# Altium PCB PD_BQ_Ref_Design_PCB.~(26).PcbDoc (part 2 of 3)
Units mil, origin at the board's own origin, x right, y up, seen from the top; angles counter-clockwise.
Board outline 2000 x 3000 mil, 4 copper layers (Top Layer, Signal Layer 1, Signal Layer 2, Bottom Layer), stack 61.2 mil thick; 124 components, 53 nets, 359 pads, 494 vias.
Unrouted connection lines stored in the file: 227.

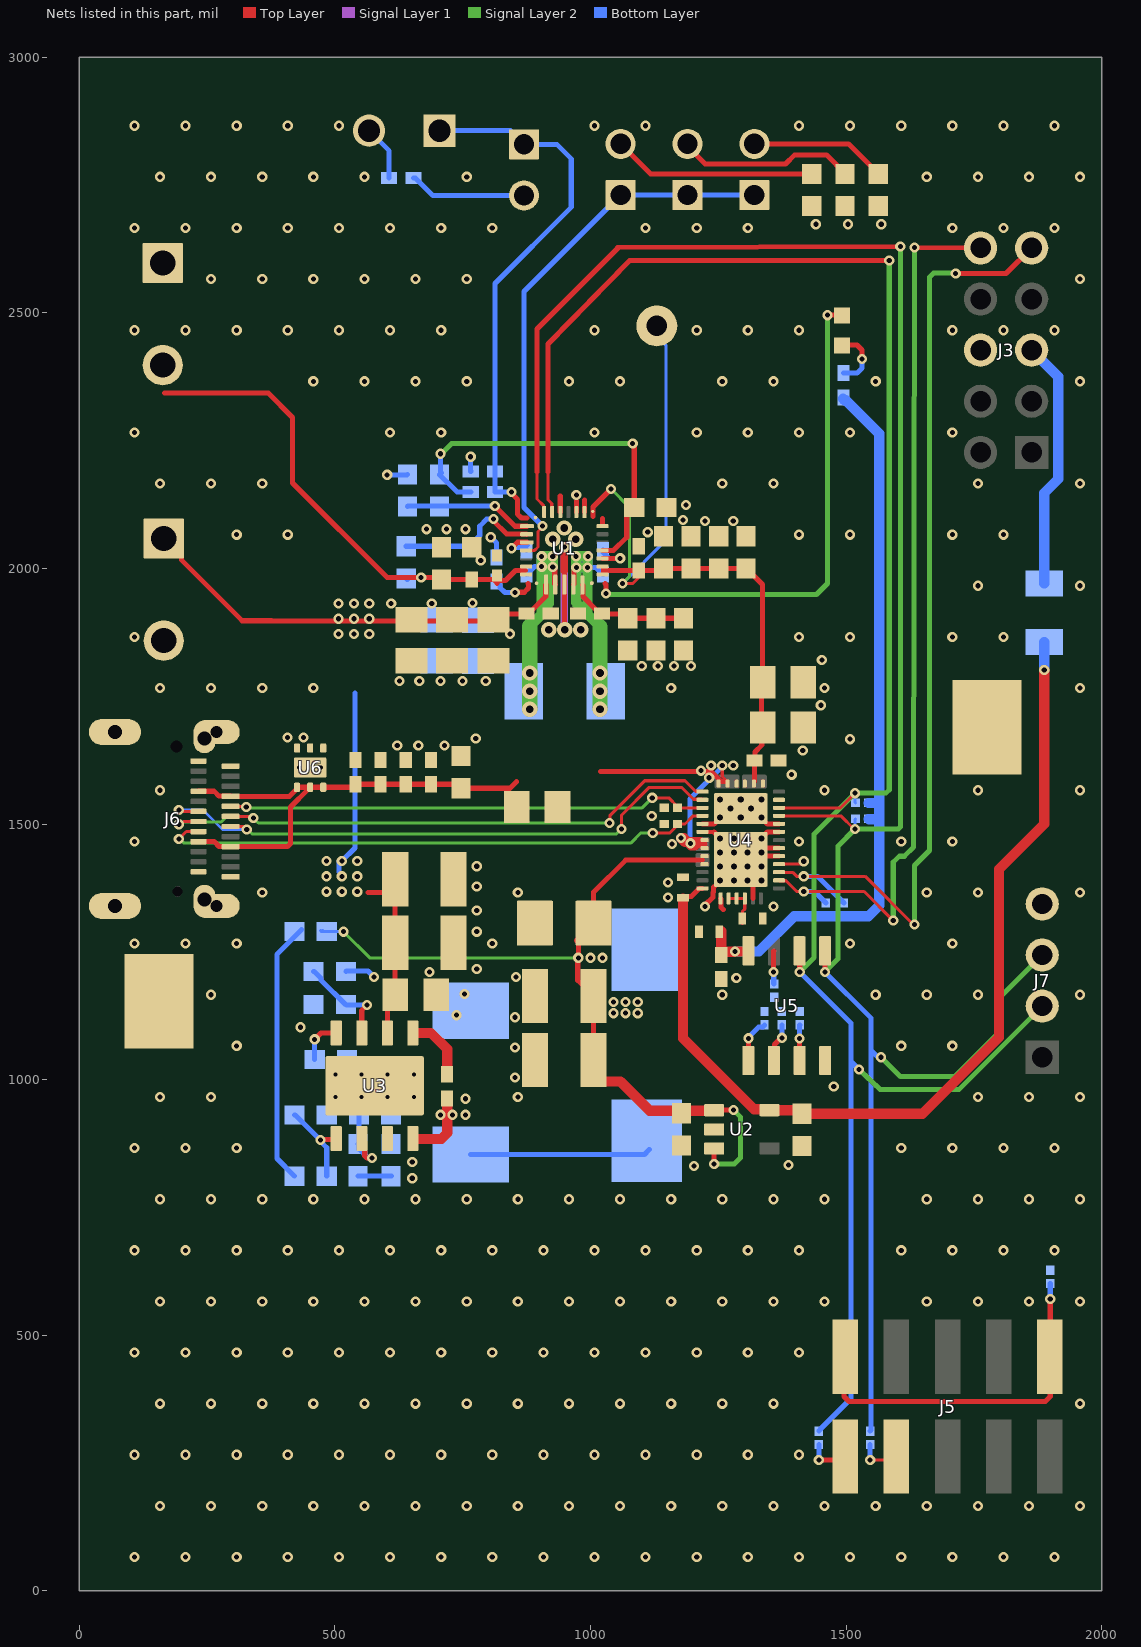
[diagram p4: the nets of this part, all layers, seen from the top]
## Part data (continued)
Logo4: library part CMP-0074769-1
LOGO5: library part CMP-0074837-1, "IEC 61010-1 Hot Surface Warning"
NT1: library part CMP-0078142-3, "Single point connection between nets.", Manufacturer=N/A
R1: library part CMP-0022736-4, "RES, 100, 1%, 0.1 W, 0603", Manufacturer=Yageo, Power_W=100mW, Supplier Part Number 1=311-100HRCT-ND, TempCo="100 ppm/C", Tolerance_%=1%, Value2=0.1W, Value_Code=100R, ValueDisplayed=100
R2: library part CMP-0026232-2, "RES, 2.21 k, 1%, 0.063 W, AEC-Q200 Grade 0, 0402", Manufacturer=Vishay-Dale, Power_W=63mW, Supplier Part Number 1=541-2.21KLCT-ND, TempCo="100 ppm/C", Tolerance_%=1%, Value2=0.063W, Value_Code=2k21, ValueDisplayed=2.21k
R3: library part CMP-0026464-2, "RES, 5.23 k, 1%, 0.063 W, AEC-Q200 Grade 0, 0402", Manufacturer=Vishay-Dale, PartNumber=CRCW04025K23FKED, Power_W=63mW, Supplier Part Number 1=541-5.23KLCT-ND, TempCo="100 ppm/C", Tolerance_%=1%, Value2=0.063W, Value_Code=5k23, ValueDisplayed=5.23k
R4: library part CMP-0022788-4, "RES, 137 k, 1%, 0.1 W, 0603", Manufacturer=Yageo, Power_W=100mW, Supplier Part Number 1=311-137KHRCT-ND, TempCo="100 ppm/C", Tolerance_%=1%, Value2=0.1W, Value_Code=137k
R5: library part CMP-0026284-2, "RES, 30.1 k, 1%, 0.063 W, AEC-Q200 Grade 0, 0402", Manufacturer=Vishay-Dale, PartNumber=CRCW040230K1FKED, Power_W=63mW, Supplier Part Number 1=541-30.1KLCT-ND, TempCo="100 ppm/C", Tolerance_%=1%, Value2=0.063W, Value_Code=30k1, ValueDisplayed=30.1k
R6: library part CMP-0022735-5, "RES, 100 k, 1%, 0.1 W, 0603", Manufacturer=Yageo, Power_W=100mW, Supplier Part Number 1=311-100KHRCT-ND, TempCo="100 ppm/C", Tolerance_%=1%, Value2=0.1W, Value_Code=100k
R7: library part CMP-0025958-3, "RES, 10.0 k, 1%, 0.063 W, AEC-Q200 Grade 0, 0402", Manufacturer=Vishay-Dale, PartNumber=CRCW040210K0FKED, Power_W=63mW, Supplier Part Number 1=541-10.0KLCT-ND, TempCo="100 ppm/C", Tolerance_%=1%, Value2=0.063W, Value_Code=10k0, ValueDisplayed=10.0k
R8: library part CMP-0023246-5, "RES, 6.04 k, 1%, 0.1 W, 0603", Manufacturer=Yageo, Power_W=100mW, Supplier Part Number 1=311-6.04KHRCT-ND, TempCo="100 ppm/C", Tolerance_%=1%, Value2=0.1W, Value_Code=6k04, ValueDisplayed=6.04k
R9: library part CMP-0022000-4, "RES, 10.5 k, 1%, 0.1 W, AEC-Q200 Grade 0, 0603", Manufacturer=Vishay-Dale, Power_W=100mW, Supplier Part Number 1=541-10.5KHCT-ND, TempCo="100 ppm/C", Tolerance_%=1%, Value2=0.1W, Value_Code=10k5, ValueDisplayed=10.5k
R10: library part CMP-0022089-4, "RES, 17.4 k, 1%, 0.1 W, AEC-Q200 Grade 0, 0603", Manufacturer=Vishay-Dale, Power_W=100mW, Supplier Part Number 1=541-17.4KHCT-ND, TempCo="100 ppm/C", Tolerance_%=1%, Value2=0.1W, Value_Code=17k4, ValueDisplayed=17.4k
R11: library part CMP-0017299-3, "RES, 10.0, 1%, 0.25 W, AEC-Q200 Grade 0, 1206", Manufacturer=Panasonic, Power_W=250mW, Supplier Part Number 1=P10.0FCT-ND, TempCo="100 ppm/C", Tolerance_%=1%, Value2=0.25W, Value_Code=10R0, ValueDisplayed=10.0
R12: library part CMP-0022483-4, "RES, 51.1, 1%, 0.1 W, AEC-Q200 Grade 0, 0603", Manufacturer=Vishay-Dale, Power_W=100mW, Supplier Part Number 1=541-51.1HCT-ND, TempCo="100 ppm/C", Tolerance_%=1%, Value2=0.1W, Value_Code=51R1, ValueDisplayed=51.1
R13: library part CMP-0022546-4, "RES, 665 k, 1%, 0.1 W, AEC-Q200 Grade 0, 0603", Manufacturer=Vishay-Dale, Power_W=100mW, Supplier Part Number 1=541-665KHCT-ND, TempCo="100 ppm/C", Tolerance_%=1%, Value2=0.1W, Value_Code=665k
R14: library part CMP-0021999-4, "RES, 10.2 k, 1%, 0.1 W, AEC-Q200 Grade 0, 0603", Manufacturer=Vishay-Dale, Power_W=100mW, Supplier Part Number 1=541-10.2KHCT-ND, TempCo="100 ppm/C", Tolerance_%=1%, Value2=0.1W, Value_Code=10k2, ValueDisplayed=10.2k
R15: library part CMP-0022036-4, "RES, 130 k, 1%, 0.1 W, AEC-Q200 Grade 0, 0603", Manufacturer=Vishay-Dale, Power_W=100mW, Supplier Part Number 1=541-130KHCT-ND, TempCo="100 ppm/C", Tolerance_%=1%, Value2=0.1W, Value_Code=130k
R16: library part CMP-0022137-4, "RES, 1.96 k, 1%, 0.1 W, AEC-Q200 Grade 0, 0603", Manufacturer=Vishay-Dale, Power_W=100mW, Supplier Part Number 1=541-1.96KHCT-ND, TempCo="100 ppm/C", Tolerance_%=1%, Value2=0.1W, Value_Code=1k96, ValueDisplayed=1.96k
R17: library part CMP-0022360-4, "RES, 37.4 k, 1%, 0.1 W, AEC-Q200 Grade 0, 0603", Manufacturer=Vishay-Dale, Power_W=100mW, Supplier Part Number 1=541-37.4KHCT-ND, TempCo="100 ppm/C", Tolerance_%=1%, Value2=0.1W, Value_Code=37k4, ValueDisplayed=37.4k
R21 R22 R24 R25: library part CMP-0027272-3, "RES, 2.20 k, 1%, 0.05 W, 0201", Manufacturer=Vishay-Dale, Power_W=50mW, Supplier Part Number 1=541-2.20KAABCT-ND, TempCo="100 ppm/C", Tolerance_%=1%, Value2=0.05W, Value_Code=2k20, ValueDisplayed=2.20k
R26 R27 R29: library part CMP-0027008-4, "RES, 0, 5%, 0.05 W, 0201", Manufacturer=Vishay-Dale, Power_W=50mW, Supplier Part Number 1=72M6743, TempCo=ppm/C, Tolerance_%=5%, Value2=0.05W, Value_Code=0000, ValueDisplayed=0
R28 R30 R31 R32: library part CMP-0027262-3, "RES, 10.0 k, 1%, 0.05 W, 0201", Manufacturer=Vishay-Dale, Power_W=50mW, Supplier Part Number 1=541-10.0KAABCT-ND, TempCo="100 ppm/C", Tolerance_%=1%, Value2=0.05W, Value_Code=10k0, ValueDisplayed=10.0k
SH-J1 SH-J2: library part CMP-0003623-1, "Shunt, 100mil, Gold plated, Black", Alternate Manufacturer=3M, Alternate PartNumber=969102-0000-DA, Manufacturer=Samtec, Supplier Part Number 1=SNT-100-BK-G-ND
TP1: library part CMP-0055137-1, "Test Point, Miniature, Red, TH", Color=Red, Manufacturer=Keystone, Supplier Part Number 1=36-5000-ND
TP2 TP3: library part CMP-0055153-1, "Test Point, Compact, SMT", Manufacturer=Keystone, Supplier Part Number 1=36-5016TR-ND
U1: library part CMP-0088656-1, "BQ2579x HotRod", Manufacturer="Texas Instruments", Operating Temperature Range=to
U2: library part CMP-0074640-3, "500-mA, Low IQ, Small Size, Low Dropout Regulator, DBV0005A (SOT-23-5)", Alternate Manufacturer="Texas Instruments"
U3: library part CMP-0067056-2, "3.5V to 28V Input, 5A, 570kHz Step-Down Converter with Eco-mode, DDA0008E (SOIC-8)", Alternate Manufacturer="Texas Instruments", Alternate PartNumber=TPS54531DDA
U4: library part CMP-0090338-5, "USB Type-C and USB PD Controller with Integrated Power Switches Optimized for Power Applications", Manufacturer="Texas Instruments", Max Supply Voltage=22V, Min Supply Voltage=3V, Operating Temperature Range="-40°C to +125°C"
U5: library part CMP-0005314-2, "256 kb I2C CMOS Serial EEPROM, SOIC-8", Manufacturer="ON Semiconductor", Supplier Part Number 1=CAT24C256WI-G-ND
U6: library part CMP-0077834-1, "22-V Precision Surge Protection Clamp, DRV0006A (WSON-6)", Alternate Manufacturer="Texas Instruments"
ZZ1: library part CMP-0003616-3

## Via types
v1: diameter 20, hole 10, Top Layer to Bottom Layer, tented both sides, 445 vias
v2: diameter 23.62, hole 11.81, Top Layer to Bottom Layer, 24 vias
v3: diameter 30, hole 15, Top Layer to Bottom Layer, tented both sides, 12 vias
v4: diameter 19.68, hole 7.87, Top Layer to Bottom Layer, tented both sides, 10 vias
v5: diameter 20, hole 10, Top Layer to Bottom Layer, 3 vias

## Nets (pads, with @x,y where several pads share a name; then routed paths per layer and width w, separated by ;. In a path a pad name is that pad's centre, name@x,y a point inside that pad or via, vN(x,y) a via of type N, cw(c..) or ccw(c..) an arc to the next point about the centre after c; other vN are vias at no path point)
AGND: C22.2 J3.6 J4.2 NT1.2 R5.1 R6.1 R7.1 R8.1 R9.1 R10.1 U1.10 U1.11 U1.13 | length 298.5
  Top Layer w10: 940.94,2141.73 941.06,2141.61 U1.13@941.06,2110.14 ; 972.44,2131.89 972.44,2110.25 U1.11@972.56,2110.14 ; 988.19,2133.86 988.31,2133.74 U1.10@988.31,2110.14
  Bottom Layer w10: J4.2@566.93,2856.3 606.3,2816.93 R7.1@606.3,2763.78 ; v1(602.36,2183.07) 640.93,2183.07 R6.1@641.92,2184.06 ; v1(765.75,2218.5) 765.75,2190.08 R5.1@765.87,2189.96 ; v1(805.12,2061.02) 816.06,2050.08 C22.2@816.06,2021.65
  other v1: 972.44,2143.7 1440.94,2673.23 1503.94,2673.23 1568.9,2673.23
BAT: C19.1 C20.1 C21.1 J2.2 R1.1 U1.22 U1.23 | length 977.6
  Top Layer w10: 167.32,2342.91 369.68,2342.91 417.32,2295.28 417.32,2167.32 602.36,1982.28 v1(668.92,1982.28) 704.84,1982.28 C21.1@708.78,1978.35 C20.1@767.83,1978.35 811.14,1978.35 817.05,1972.44 ; 817.05,1970.47 817.05,1972.44 ; 873.15,1996.06 853.46,1996.06 833.89,1976.49 821.1,1976.49 817.05,1972.44
  Bottom Layer w10: R1.1@639.76,1980.31 641.73,1978.35 645.67,1982.28 v1(668.92,1982.28)
C_CC1: C42.1 J6.A5 U4.28 | length 942.2
  Top Layer w6: J6.A5@296.26,1534.45 296.75,1533.96 326.28,1533.96 v1(326.77,1533.46) ; v1(1120.87,1551.18) 1153.44,1551.18 1170.47,1534.15 C42.1@1170.47,1531.5 1219.12,1531.5 U4.28@1219.3,1531.68
  Signal Layer 2 w6: v1(326.77,1533.46) 328.74,1531.5 1101.18,1531.5 v1(1120.87,1551.18)
C_CC2: C41.1 J6.B5 U4.29 | length 1095.8
  Top Layer w6: v1(194.88,1470.47) 209.65,1485.24 J6.B5@233.27,1485.24 ; v1(1122.05,1482.28) 1155.41,1482.28 1170.47,1497.35 C41.1@1170.47,1500 1185.04,1500 1200.97,1515.93 U4.29@1219.3,1515.93
  Signal Layer 2 w6: v1(194.88,1470.47) 197.52,1470.47 205.4,1462.6 1078.74,1462.6 1098.43,1482.28 v1(1122.05,1482.28)
C_USB_N: J6.A7 J6.B7 U4.27 | length 1182
  Top Layer w6: v1(194.88,1527.56) 197.83,1524.61 J6.B7@233.27,1524.61 ; J6.A7@296.26,1495.08 321.85,1495.08 v1(327.7,1489.23) ; v1(1061.02,1490.16) 1061.02,1517.72 1114.98,1571.68 1178.32,1571.68 1201.64,1548.36 1218.36,1548.36 U4.27@1219.3,1547.43
  Signal Layer 2 w6: v1(327.7,1489.23) 329.3,1489.23 338.21,1480.32 1050.51,1480.32 v1@1060.69,1490.49
  Bottom Layer w6: v1(194.88,1527.56) 242.13,1527.56 280.45,1489.23 v1(327.7,1489.23) ; v1@1060.35,1490.16 v1(1061.02,1490.16)
C_USB_P: J6.A6 J6.B6 U4.26 | length 1175.4
  Top Layer w6: v1(194.88,1499.56) 198.67,1499.56 204.03,1504.92 J6.B6@233.27,1504.92 ; J6.A6@296.26,1514.76 333.81,1514.76 336.76,1511.81 v1(340.55,1511.81) ; v1(1037.4,1501.97) 1037.95,1502.51 1037.95,1516.29 1106.3,1584.65 1185.04,1584.65 1205.58,1564.11 1218.36,1564.11 U4.26@1219.3,1563.17
  Signal Layer 2 w6: v1(194.88,1499.56) 198.67,1499.56 203.05,1503.94 277.56,1503.94 288.39,1514.76 330.04,1514.76 330.31,1514.49 337.87,1514.49 v1(340.55,1511.81) ; v1@339.07,1513.29 350.39,1501.97 v1(1037.4,1501.97)
GND: C2.1 C3.1 C4.1 C5.1 C6.2 C8.1 C9.1 C10.1 C11.2 C12.2 C13.2 C14.2 C15.2 C16.2 C17.2 C18.2 C19.2 C20.2 C21.2 C23.1 C24.1 C26.2 C27.2 C28.2 C29.2 C30.2 C31.2 C33.2 C34.2 C35.2 C36.2 C37.2 C38.2 C39.2 C40.2 C41.2 C42.2 C43.2 C44.2 C45.1 C46.1 C47.1 C48.1 D2.2 J1.2 J2.1 J6.A1 J6.A12 J6.B1 J6.B12 J6.S1 J6.S2 J6.S3 J6.S4 J7.4 NT1.1 R15.1 R16.1 R17.1 R28.1 R29.1 R30.1 R31.1 R32.1 TP2.1 TP3.1 U1.27 U2.2 U3.7 U3.9@577.76,987.91 U4.10 U4.11 U4.12 U4.14 U4.18 U4.31 U4.39 U5.4 U6.1 U6.2 U6.3 U6.7@451.77,1610.24 | length 871.8
  Top Layer w6: U4.10@1368.91,1421.44 1411.6,1421.44 v1(1417.32,1427.17)
  Top Layer w8: U4.31@1219.3,1484.43 1241.74,1484.43
  Top Layer w10: 948.94,1996.06 U1.27@948.94,1968.4 948.94,1879.92 v3(949.92,1879.92) ; v1(1224.41,1338.58) 1224.41,1341.29 1239.73,1356.61 1239.73,1365.89 1241.11,1367.27 1241.11,1376.32 1281.21,1416.42 1294.1,1429.31 U4.39@1294.1,1430.69 ; 1241.74,1484.43 1281.21,1444.96 U4.39@1294.1,1432.07 ; U4.39@1307.69,1417.11 U4.39@1294.1,1430.69 ; U4.39@1307.69,1444.28 U4.39@1294.1,1430.69 ; U4.39@1315.66,1453.63 1346.46,1484.43 U4.14@1368.91,1484.43 ; U4.39@1316.35,1452.94 U4.12@1368.91,1452.94 U4.39@1334.26,1452.94 ; 1317.72,1354.51 U4.39@1317.72,1407.07 ; U4.39@1334.26,1437.19 U4.11@1368.91,1437.19
  Top Layer w15: 948.94,1996.06 v1@948.94,2041.53
  Signal Layer 1 w15: v1(948.94,2041.55) 949.06,2041.43 949.06,1880.79 v3(949.92,1879.92)
  other v1: 108,66 208,66 308,66 408,66 508,66 608,66 708,66 808,66 908,66 1008,66 1108,66 1208,66 1308,66 1408,66 1508,66 1608,66 1708,66 1808,66 1908,66 158,166 258,166 358,166 458,166 558,166 658,166 758,166 858,166 958,166 1058,166 1158,166 1258,166 1358,166 1458,166 1558,166 1658,166 1758,166 1858,166 1958,166 108,266 208,266 308,266 408,266 508,266 608,266 708,266 808,266 908,266 1008,266 1108,266 1208,266 1308,266 1408,266 158,366 258,366 358,366 458,366 558,366 658,366 758,366 858,366 958,366 1058,366 1158,366 1258,366 1358,366 1958,366 108,466 208,466 308,466 408,466 508,466 608,466 708,466 808,466 908,466 1008,466 1108,466 1208,466 1308,466 1408,466 158,566 258,566 358,566 458,566 558,566 658,566 758,566 858,566 958,566 1058,566 1158,566 1258,566 1358,566 1458,566 1658,566 1758,566 1858,566 1958,566 108,666 208,666 308,666 408,666 508,666 608,666 708,666 808,666 908,666 1008,666 1108,666 1208,666 1308,666 1408,666 1608,666 1708,666 1808,666 1908,666 158,766 258,766 358,766 458,766 558,766 658,766 758,766 858,766 958,766 1058,766 1158,766 1258,766 1358,766 1458,766 1658,766 1758,766 1858,766 1958,766 651.57,807.09 1202.76,830.71 1387.48,832.68 651.57,838.58 108,866 208,866 308,866 1608,866 1708,866 1808,866 1908,866 158,966 258,966 858,966 1758,966 1858,966 1958,966 1476.06,986.22 852.36,1003.94 852.36,1062.99 308,1066 1608,1066 1708,1066 433.07,1102.36 852.36,1122.05 738.19,1125.98 258,1166 1258,1166 1558,1166 1658,1166 1758,1166 1958,1166 753.94,1167.32 1285.43,1198.82 854.33,1200.79 685.04,1210.63 777.56,1216.54 108,1266 208,1266 308,1266 808,1266 1508,1266 1708,1266 777.56,1289.37 777.56,1330.71 1358.27,1338.58 1151.57,1356.3 358,1366 858,1366 1658,1366 1758,1366 1958,1366 777.56,1377.95 1151.57,1385.83 777.56,1417.32 108,1466 1408,1466 1608,1466 1708,1466 1120.08,1515.75 158,1566 1458,1566 1758,1566 1958,1566 1393.7,1596.46 1415.35,1643.7 622.05,1653.54 663.39,1653.54 714.57,1653.54 1508,1666 775.59,1667.32 407.48,1669.29 438.98,1669.29 1450.79,1732.28 158,1766 258,1766 358,1766 458,1766 1158,1766 1458,1766 1958,1766 626.27,1779.52 665.35,1779.53 706.69,1779.53 750,1779.53 795.28,1779.53 1100.39,1809.06 1131.89,1809.06 1163.39,1809.06 1196.85,1809.06 1452.76,1820.87 108,1866 1408,1866 1508,1866 1708,1866 1808,1866 1758,1966 1958,1966 785.43,2015.75 308,2066 408,2066 1408,2066 1508,2066 1708,2066 1808,2066 1112.2,2070.87 679.13,2076.77 718.5,2076.77 755.91,2076.77 1224.41,2092.52 1279.53,2092.52 1181.1,2094.49 1187.01,2124.02 158,2166 258,2166 358,2166 1258,2166 1358,2166 1758,2166 1958,2166 108,2266 608,2266 708,2266 1008,2266 1208,2266 1308,2266 1408,2266 1508,2266 1708,2266 458,2366 558,2366 658,2366 758,2366 958,2366 1058,2366 1258,2366 1358,2366 1558,2366 1958,2366 108,2466 208,2466 308,2466 408,2466 508,2466 608,2466 708,2466 1008,2466 1208,2466 1308,2466 1408,2466 1708,2466 1808,2466 1908,2466 258,2566 358,2566 458,2566 558,2566 658,2566 758,2566 1958,2566 108,2666 208,2666 308,2666 408,2666 508,2666 608,2666 708,2666 808,2666 1108,2666 1208,2666 1308,2666 1708,2666 1808,2666 1908,2666 158,2766 258,2766 358,2766 458,2766 558,2766 758,2766 1658,2766 1758,2766 1858,2766 1958,2766 108,2866 208,2866 308,2866 408,2866 508,2866 1008,2866 1108,2866 1408,2866 1508,2866 1608,2866 1708,2866 1808,2866 1908,2866
  other v2: 1253.95,1389.35 1280.72,1389.35 1307.49,1389.35 1334.26,1389.35 1253.95,1416.91 1280.72,1416.91 1307.49,1416.91 1334.26,1416.91 1253.95,1444.47 1280.72,1444.47 1307.49,1444.47 1334.26,1444.47 1253.95,1472.03 1280.72,1472.03 1307.49,1472.03 1334.26,1472.03
  other v3: 918.43,1879.92 981.42,1879.92 926.29,2057.07 971.57,2057.09 948.92,2078.94
  other v4: 500.98,966.26 552.17,966.26 603.35,966.26 654.53,966.26 500.98,1009.57 552.17,1009.57 603.35,1009.57 654.53,1009.57 430.12,1610.24 473.43,1610.24
I2C1_SCL: J3.9 R21.1 U4.9 | length 1911.4
  Top Layer w6: U4.9@1368.91,1405.69 1369.84,1404.76 1396.54,1404.76 1403.65,1397.64 v1(1417.32,1397.64) 1537.4,1397.64 1632.87,1302.17 v5@1633.86,1301.18
  Top Layer w10: v5(1714.57,2576.77) 1812.99,2576.77 J3.9@1863.19,2626.97
  Signal Layer 2 w10: v5(1633.86,1303.15) 1633.86,1418.88 1663.39,1448.41 1663.39,2569.65 1671.26,2577.52 1713.82,2577.52 v5(1714.57,2576.77)
  Bottom Layer w10: v1(1417.32,1397.64) 1444.09,1397.64 R21.1@1496.06,1345.67
I2C1_SDA: J3.10 R22.1 U4.8 | length 1783.2
  Top Layer w6: U4.8@1368.91,1389.94 1369.84,1389.01 1382.65,1389.01 1403.54,1368.11 v1(1417.32,1368.11) 1535.43,1368.11 v1(1592.52,1311.02) v1@1592.52,1309.06
  Top Layer w10: v5(1633.86,2627.95) J3.10@1763.19,2626.97
  Signal Layer 2 w10: v1(1592.52,1311.02) 1592.52,1425.2 1604.33,1437.01 1614.17,1437.01 1631.89,1454.72 1633.86,2629.92 v5(1633.86,2627.95)
  Bottom Layer w10: v1(1417.32,1368.11) 1438.19,1368.11 R22.1@1460.63,1345.67
I2C_SCL: J7.2 R24.2 R26.1 U1.14 U4.17 U5.6 | length 4218
  Top Layer w6: 917.32,2188.98 917.32,2133.86 924.38,2126.8 924.38,2111.07 U1.14@925.31,2110.14 ; U4.17@1368.91,1531.68 1489.12,1531.68 v1(1517.72,1560.27)
  Top Layer w10: 917.32,2188.98 917.32,2438.98 1076.77,2602.36 v1(1584.65,2602.36) ; v1(1409.45,1210.63) U5.6@1409.45,1251.5
  Signal Layer 2 w10: v1(1409.45,1210.63) 1437.32,1238.5 1437.32,1479.88 v1(1517.72,1560.27) 1577.99,1560.27 1584.65,1566.93 v1(1584.65,2602.36) ; v1(1525.59,1019.68) 1566.93,980.32 1720.47,980.32 J7.2@1883.86,1143.7
  Bottom Layer w6: v1(1517.72,1560.27) 1517.72,1542.13 R24.2@1518.5,1541.34
  Bottom Layer w10: v1(1409.45,1210.63) 1509.84,1110.24 1509.84,1033.46 ; R26.1@1446.85,312.2 1446.85,312.99 1450.12,316.26 1450.21,316.26 1509.84,375.9 1509.84,1033.46 ; v1(1525.59,1019.68) 1511.81,1033.46 1509.84,1033.46
I2C_SDA: J7.3 R25.2 R27.1 U1.15 U4.16 U5.5 | length 4321.3
  Top Layer w6: 895.67,2188.98 895.67,2135.83 908.63,2122.87 908.63,2111.07 U1.15@909.57,2110.14 ; U4.16@1368.91,1515.93 1489.98,1515.93 1515.75,1490.16 v1(1517.72,1490.16)
  Top Layer w10: 895.67,2188.98 895.67,2468.5 1055.12,2627.95 ; 1053.15,2627.95 v1@1604.33,2629.92 ; v1(1458.66,1210.63) U5.5@1458.66,1251.5
  Signal Layer 2 w10: v1(1458.66,1210.63) 1484.25,1236.22 1484.25,1456.69 v1(1517.72,1490.16) 1602.36,1490.16 1606.3,1494.09 v1(1606.3,2629.92) ; v1(1568.5,1043.7) 1606.3,1005.91 1712.6,1005.91 1797.24,1090.55 1797.24,1157.09 J7.3@1883.86,1243.7
  Bottom Layer w6: v1(1517.72,1490.16) 1517.72,1509.05 R25.2@1518.5,1509.84
  Bottom Layer w10: v1(1458.66,1210.63) 1549.21,1120.08 1549.21,1057.09 ; R27.1@1547.24,312.2 1549.21,314.17 1549.21,1057.09 ; v1(1568.5,1043.7) 1562.6,1043.7 1549.21,1057.09
ILIM_HIZ: R4.1 R6.2 U1.17 | length 250.9
  Top Layer w10: v1(812.99,2122.04) 852.46,2082.58 U1.17@876.1,2082.58
  Bottom Layer w10: R6.2@641.92,2121.06 642.9,2122.05 802.68,2122.05 v1(812.99,2122.04)
LDO_1V5: C37.1 U4.2 U4.3 U4.4 | length 83
  Top Layer w6: U4.2@1270.48,1354.51 U4.3@1286.23,1354.51 U4.4@1301.98,1354.51 1301.98,1333.47 1297.24,1328.74 1297.24,1305.43 C37.1@1296.93,1305.12
LDO_3V3: C36.1 C43.1 R2.2 R21.2 R22.2 R24.1 R25.1 U4.1 U5.8 | length 1507.2
  Top Layer w10: U4.1@1254.73,1354.51 1255.8,1353.45 1255.8,1336.72 1259.84,1332.68
  Top Layer w20: C43.1@1255.91,1244.09 1255.91,1248.03 C43.1@1257.72,1249.84 ; C36.1@1255.91,1290.2 1255.91,1249.84 C43.1@1257.72,1249.84 ; U5.8@1309.05,1251.89 1307.79,1250.63 v1(1282.76,1250.63) 1282.13,1250 1269.43,1250 1269.27,1249.84 C43.1@1257.72,1249.84
  Bottom Layer w20: v1@1283.46,1250.63 1329.37,1250.63 1398.43,1319.69 1468.5,1319.69 1498.03,1319.69 1527.56,1319.69 1544.09,1319.69 1564.96,1340.55 1564.96,1509.35 ; R2.2@1494.09,2331.69 1496.89,2328.9 1499.84,2328.9 1564.96,2263.78 1564.96,1541.91 ; R25.1@1544.49,1509.84 1544.98,1509.35 1564.96,1509.35 ; R24.1@1544.49,1541.34 1564.39,1541.34 1564.96,1541.91 ; 1564.96,1509.35 1564.96,1541.91
NetC1_1: C1.1 U1.4 | length 76.9
  Top Layer w10: U1.4@1023.74,2019.59 1058.09,2019.59 v1(1058.19,2019.69)
  Bottom Layer w10: C1.1@1024.72,2035.43 1024.72,2031.5 1036.64,2019.59 1058.09,2019.59 v1(1058.19,2019.69)
NetC1_2: C1.2 L1.1 U1.28 | length 640.5
  Top Layer w10: U1.28@966.65,1968.4 967.72,1969.47 967.72,1997.24 v1(972.44,2001.97)
  Signal Layer 2 w20: 1018.82,1885.83 994.42,1910.22 ; v1(972.44,2001.97) 972.44,2022.76 v1(971.57,2023.62) v1(995.2,2023.62) 994.09,2022.52 v1(994.09,2001.97) ; v1(972.44,2001.97) v1(994.09,2001.97) ; v1(972.44,2001.97) 972.44,1933.97 971.56,1933.09 994.42,1910.22 ; v1(994.09,2001.97) 994.42,2001.64 994.42,1910.22
  Signal Layer 2 w30: v3(1018.82,1724.41) 1018.82,1885.83
  Bottom Layer w10: v1(994.09,2001.97) 1010.94,2001.97 C1.2@1024.72,1988.19
  Bottom Layer w20: v1@971.57,2003.74 972.44,2002.87 v1(972.44,2001.97) v1(994.09,2001.97) 994.09,2022.52 v1(995.2,2023.62) v1(971.57,2023.62) v1@971.57,2003.74
  other v3: 1018.82,1759.84 1018.82,1795.44
NetC7_1: C7.1 U1.19 | length 77
  Top Layer w10: v1(845.59,2039.37) 857.3,2051.08 U1.19@875.71,2051.08
  Bottom Layer w10: v1(845.59,2039.37) 847.09,2040.87 869.68,2040.87 C7.1@875.12,2035.43 ; C7.1@870.35,2039.37 C7.1@877.17,2046.18
NetC7_2: C7.2 L1.2 U1.26 | length 624.4
  Top Layer w10: v1(926.3,2002.54) 926.3,2001.23 930.16,1997.37 930.16,1969.47 U1.26@931.22,1968.4
  Signal Layer 2 w20: 881.02,1887.04 904.65,1910.67 v1(904.65,2003.36) 925.47,2003.36 v1(926.3,2002.54) ; 904.65,1917.32 918.43,1931.1 918.43,1994.66 v1(926.3,2002.54) ; v1@904.65,2004.35 v1(904.65,2023.62) v1(926.3,2023.62) v1(926.3,2002.54)
  Signal Layer 2 w30: v3(881.02,1724.41) v3(881.02,1759.84) v3(881.02,1795.3) 881.02,1887.04
  Bottom Layer w10: C7.2@875.12,1988.19 890.87,2003.94 891.44,2003.36 v1(904.65,2003.36)
  Bottom Layer w20: v1(904.65,2003.36) 925.47,2003.36 v1(926.3,2002.54) v1(926.3,2023.62) v1(904.65,2023.62) v1(904.65,2003.36)
NetC22_1: C22.1 U1.24 | length 87.7
  Top Layer w10: v1(852.36,1952.76) 853.01,1953.4 870.73,1953.4 878.91,1961.58 878.91,1969.52 877.95,1970.47
  Bottom Layer w10: C22.1@816.06,1974.41 822.87,1967.6 822.87,1962.55 832.67,1952.76 v1(852.36,1952.76)
NetC25_1: C25.1 U3.1 | length 129.4
  Top Layer w20: U3.1@652.76,1091.26 688.27,1091.26 719.74,1059.78 C25.1@719.74,1010.38
NetC25_2: C25.2 D2.1 L2.1 U3.8 | length 493.1
  Top Layer w20: U3.8@652.76,884.57 652.87,884.57 653.58,883.86 708.03,883.86 719.74,895.57 C25.2@719.74,963.14
  Bottom Layer w10: D2.1@765.75,853.6 1105.57,853.6 L2.1@1115.16,863.19
  other v1: 706.69,931.1 730.32,931.1 755.91,931.1 755.91,962.6
NetC32_1: C32.1 C34.1 U3.6 | length 164.6
  Top Layer w10: U3.6@552.76,884.57 558.58,878.74 558.58,850.87 562.99,846.46 v1(572.83,846.46)
  Bottom Layer w10: C32.1@546.79,874.02 C32.1@546.79,872.56 ; C34.1@547.24,931.1 547.24,875.98 C32.1@545.28,874.02 C32.1@546.79,872.56 ; C32.1@547.98,864.41 549.51,869.93 C32.1@546.79,872.56 ; v1(572.83,846.46) 565.06,846.46 546.79,864.74 C32.1@546.79,872.56
NetC32_2: C32.2 R17.2 | length 65.9
  Bottom Layer w10: C32.2@545.28,811.02 R17.2@611.22,811.02
NetC33_1: C33.1 U3.4 | length 86.7
  Top Layer w10: v1(460.63,1078.74) 473.15,1091.26 U3.4@502.76,1091.26
  Bottom Layer w10: C33.1@460.63,1039.37 v1(460.63,1078.74)
NetC44_1: C44.1 C45.2 C46.2 C47.2 C48.2 J6.A4 J6.A9 J6.B4 J6.B9 L3.1 U6.4 U6.5 U6.6 | length 961.1
  Top Layer w10: J6.B4@233.27,1465.55 264.02,1465.55 273.54,1456.02 295.94,1456.02 J6.A9@296.26,1455.71 311.38,1455.71 407.53,1455.71 413.39,1461.57 413.39,1533.46 447.91,1567.99 450.87,1567.99 451.77,1568.9 U6.5@451.77,1571.85 ; J6.B9@233.27,1563.98 264.02,1563.98 273.54,1554.45 295.94,1554.45 J6.A4@296.26,1554.13 411.42,1554.13 426.18,1568.9 U6.4@426.18,1571.85 447.91,1571.85 U6.5@451.77,1571.85 ; 855.67,1582.68 842.87,1569.88 C44.1@747.05,1569.88 739.17,1577.76 C48.2@687.99,1577.76 C47.2@638.78,1577.76 C46.2@589.57,1577.76 C45.2@540.35,1577.76 534.45,1571.85 U6.6@477.36,1571.85 U6.5@451.77,1571.85
NetD1_1: D1.1 R2.1 | length 119.8
  Top Layer w10: D1.1@1492.13,2436.02 1493.11,2437.01 1521.65,2437.01 1531.5,2427.17 v1(1531.5,2409.45)
  Bottom Layer w10: R2.1@1495.08,2381.89 1521.65,2381.89 1531.5,2391.73 v1(1531.5,2409.45)
NetJ3_5: J3.5 R11.1 | length 489.2
  Bottom Layer w20: J3.5@1863.19,2426.97 1915,2375.16 1915,2174.84 1887.8,2147.64 R11.1@1887.8,1970.47
NetJ5_1: J5.1 R26.2 | length 85
  Top Layer w10: v1(1446.85,255.91) 1491.67,255.91 J5.1@1498.64,262.87
  Bottom Layer w10: v1(1446.85,255.91) R26.2@1446.85,286.22
NetJ5_2: J5.2 J5.10 R29.2 | length 712.5
  Top Layer w10: J5.2@1498.64,457.75 1496.16,455.27 1496.16,379.83 1505.91,370.08 1889.76,370.08 1899.51,379.83 1899.51,456.88 J5.10@1898.64,457.75 1899.61,458.72 v1(1899.61,570.87)
  Bottom Layer w10: v1(1899.61,570.87) R29.2@1899.61,601.18
NetJ5_3: J5.3 R27.2 | length 84.6
  Top Layer w6: v1(1547.24,255.91) 1591.67,255.91 J5.3@1598.64,262.87
  Bottom Layer w10: v1(1547.24,255.91) R27.2@1547.24,286.22
NetJP1_2: JP1.2 R8.2 | length 398.4
  Top Layer w10: JP1.2@1059.06,2830.51 1117.91,2771.65 R8.2@1433.07,2771.65
NetJP2_2: JP2.2 R9.2 | length 350.8
  Top Layer w10: JP2.2@1189.96,2830.51 1189.96,2825.79 1224.76,2790.98 1381.73,2790.98 1399.81,2809.06 1461.61,2809.06 1498.03,2772.64 R9.2@1498.03,2771.65
NetJP3_2: JP3.2 R10.2 | length 267.1
  Top Layer w10: JP3.2@1320.87,2830.51 1505.12,2830.51 1562.99,2772.64 R10.2@1562.99,2771.65
NetJP4_2: JP4.2 R7.2 | length 230.7
  Bottom Layer w10: R7.2@653.54,2763.78 657.48,2763.78 691.73,2729.53 JP4.2@870.08,2729.53
NetR1_2: R1.2 U1.18 | length 281.9
  Top Layer w10: v1(810.16,2096.46) 810.16,2093.39 835.97,2067.58 874.37,2067.58 U1.18@875.12,2066.83
  Bottom Layer w10: R1.2@639.76,2043.31 761.81,2043.31 783.46,2064.96 783.46,2082.58 783.41,2082.63 797.24,2096.46 v1(810.16,2096.46)
NetR12_1: R12.1 R14.2 | length 516.5
  Bottom Layer w10: R14.2@421.26,811.02 386.81,845.47 386.81,1245.08 R12.1@435.04,1293.31
NetR13_1: R13.1 R15.2 U3.3 | length 192.6
  Top Layer w10: U3.3@552.76,1091.26 552.76,1135.43 v1(562.99,1145.67)
  Bottom Layer w10: R13.1@458.66,1211.61 459.65,1211.61 473.35,1197.91 473.35,1193.98 520.67,1146.65 R15.2@521.65,1146.65 522.64,1145.67 v1(562.99,1145.67)
NetR14_1: R14.1 R16.2 U3.5 | length 179
  Top Layer w10: v1(471.95,881.89) 472.82,882.77 500.95,882.77 U3.5@502.76,884.57
  Bottom Layer w10: R16.2@421.26,931.1 422.24,931.1 471.46,881.89 v1(471.95,881.89) 471.95,879.18 484.25,866.88 R14.1@484.25,811.02
NetR28_2: R28.2 | length 66
  Top Layer w10: v1@1358.66,1211.02 v1(1358.27,1210.63) 1358.27,1251.11 1359.05,1251.89
  Bottom Layer w10: v1(1358.27,1210.63) 1358.76,1210.14 1358.76,1187.7 R28.2@1359.25,1187.2
NetR30_2: R30.2 U5.1 | length 87.4
  Top Layer w10: U5.1@1309.05,1037.33 v1(1309.06,1080.71)
  Bottom Layer w10: v1(1309.06,1080.71) 1309.06,1082.68 1329.41,1103.03 1337.28,1103.03 1340.55,1106.3 R30.2@1340.55,1107.09
NetR31_2: R31.2 U5.2 | length 76.5
  Top Layer w10: U5.2@1359.05,1037.33 1360.24,1038.51 1360.24,1068.9 1373.03,1081.69 v1(1375,1081.69)
  Bottom Layer w10: v1@1374.51,1082.18 R31.2@1374.51,1106.59
NetR32_2: R32.2 U5.3 | length 69.9
  Top Layer w10: U5.3@1409.05,1037.33 1409.14,1037.42 1409.14,1080.42 v1(1409.23,1080.51)
  Bottom Layer w10: v1(1409.23,1080.51) 1409.34,1080.62 1409.34,1106.98 R32.2@1409.45,1107.09
NetU4_15: U4.15 U4.30 U4.40 | length 233.7
  Top Layer w10: U4.30@1219.3,1500.18 1242.13,1500.18 U4.40@1272.06,1530.1 ; U4.40@1254.14,1512.19 U4.40@1272.06,1530.1 ; U4.15@1368.91,1500.18 1346.07,1500.18 ; U4.40@1272.06,1530.1 v2(1274.02,1530.1) U4.40@1294.1,1530.1 v2(1314.18,1530.1) 1316.15,1530.1 1346.07,1500.18 ; 1346.07,1500.18 1334.06,1512.19 1346.07,1500.18
  other v2: 1253.95,1512.39 1294.1,1512.39 1334.26,1512.39 1253.95,1547.82 1294.1,1547.82 1334.26,1547.82
P3V3: C24.2 C35.1 R11.2 U2.5 U4.38 | length 1869
  Top Layer w10: C35.1@1181.1,1355.98 1183.6,1358.48 1197.84,1358.48 1213.55,1374.2 U4.38@1219.3,1374.2
  Top Layer w20: C35.1@1181.1,1354.33 1181.1,1080.71 1319.94,941.87 1348.58,941.87 U2.5@1350.39,940.06 ; U2.5@1352.2,940.06 1406.67,940.06 C24.2@1413.55,933.17 1649.7,933.17 1799.21,1082.68 1799.21,1411.42 1887.8,1500 v1(1887.8,1801.18)
  Bottom Layer w20: v1(1887.8,1801.18) R11.2@1887.8,1856.3
PMID: C8.2 C9.2 C10.2 C11.1 U1.29 | length 238.5
  Top Layer w10: U1.29@984.37,1967.42 985.28,1966.51 985.28,1944.96 1012.01,1918.23 1012.01,1916.26 1017.83,1910.43 1065.08,1910.43 C10.2@1072.95,1902.56 C9.2@1128.07,1902.56 C8.2@1182.2,1902.56
PP5V: C23.2 C26.1 C27.1 C28.1 L2.2 R12.2 U2.1 U2.3 U4.34 U4.35 | length 1669.2
  Top Layer w10: C28.1@1005.91,1038.39 1006.3,1038.78 1006.3,1163.39 975.32,1194.37 975.32,1237.13 v1(976.38,1238.19) 976.38,1268.31 972.44,1272.24 C26.1@1006.3,1306.1 ; C26.1@1023.03,1289.37 C26.1@1006.3,1306.1 ; 1219.3,1429.31 1069.08,1429.31 1006.3,1366.54 C26.1@1006.3,1306.1 ; v1(1242.13,834.65) U2.3@1242.13,865.25 ; U2.1@1242.13,940.06 1242.29,940.22 1279.99,940.22 v1(1280.16,940.39)
  Top Layer w20: C28.1@1005.91,1038.39 1005.91,1011.65 1021.5,996.06 1059.06,996.06 1116.14,938.98 1173.32,938.98 C23.2@1178.15,934.15 1182.98,938.98 1241.05,938.98 U2.1@1242.13,940.06
  Signal Layer 2 w6: v1(516.96,1289.37) 568.14,1238.19 v1(976.38,1238.19)
  Signal Layer 2 w10: v1(1242.13,834.65) 1281.5,834.65 1293.31,846.46 1293.31,927.17 1280.16,940.31 v1(1280.16,940.39)
  Bottom Layer w6: R12.2@472.44,1291.34 474.41,1289.37 476.38,1291.34 478.35,1289.37 v1(516.96,1289.37)
  other v1: 1045.28,1129.92 1068.9,1129.92 1092.52,1129.92 1045.28,1151.57 1068.9,1151.57 1092.52,1151.57 1000,1238.19 1023.62,1238.19
PPHV: C2.2 C3.2 C4.2 C5.2 C6.1 C38.1 C39.1 C40.1 TP1.1 U1.2 U1.3 U1.8 U1.9 U4.20 U4.21 U4.22 | length 1633.6
  Top Layer w6: 1022.76,2098.43 1023.74,2097.44 ; U1.2@1023.74,1988.09 1023.74,1996.06 U1.3@1023.74,2003.84 ; v1(1062.99,1970.47) 1082.8,1970.47 1101.5,1989.17 C6.1@1094.61,1996.06
  Top Layer w10: 1005.04,2101.41 1005.04,2120.08 ; U1.9@1005.04,2111.61 1005.04,2120.08 ; U1.8@1023.74,2084.65 1023.74,2097.44 ; 1026.69,1996.06 1049.59,1996.06 1049.9,1995.75 1066.47,1995.75 1066.79,1996.06 C6.1@1094.61,1996.06 1138.9,1996.06 C5.2@1142.83,2000 C4.2@1196.97,2000 C3.2@1251.1,2000 1305.24,2000 1336.78,1968.46 1336.78,1799.14 1334.98,1797.34 1334.98,1712.36 1336.78,1710.56 1335.27,1709.04 1335.27,1654.17 1322.06,1640.96 1322.06,1621.33 1320.74,1620 U4.21@1320.74,1582.86 ; v1(1040.47,2155.51) 1005.04,2120.08
  Signal Layer 2 w6: v1(1040.47,2155.51) 1076.19,2119.8 1076.19,1983.67 v1(1062.99,1970.47)
  Bottom Layer w6: v1(1062.99,1970.47) 1147.64,2055.12 1147.64,2436.67 1129.92,2454.39 TP1.1@1129.92,2474.41
PROG: JP1.1 JP2.1 JP3.1 U1.20 | length 1073.5
  Top Layer w6: U1.20@874.13,2035.33 890.9,2035.33 897.39,2041.83 897.39,2072.16 906.44,2081.21 v1(906.44,2082.85)
  Bottom Layer w10: v1(906.44,2082.85) 870.08,2119.21 870.08,2541.54 JP1.1@1059.06,2730.51 JP2.1@1189.96,2730.51 JP3.1@1320.87,2730.51
REGN: C18.1 R3.2 R4.2 U1.5 | length 752.8
  Top Layer w10: U1.5@1023.74,2035.33 1045.41,2035.33 1071.06,2060.99 1071.06,2105.39 1084.76,2119.09 C18.1@1085.75,2119.09 1085.75,2241.02 v1(1082.68,2244.09)
  Signal Layer 2 w10: v1(706.69,2224.41) 708.66,2224.41 728.35,2244.09 v1(1082.68,2244.09)
  Bottom Layer w10: R4.2@704.78,2184.06 R4.2@704.78,2183.07 ; v1(706.69,2224.41) 706.69,2188.92 708.66,2186.96 R4.2@704.78,2183.07 ; R3.2@765.87,2149.61 739.29,2149.61 719.53,2169.37 718.48,2169.37 R4.2@704.78,2183.07
STAT: D1.2 U1.1 | length 1022.6
  Top Layer w10: 1028.73,1970.41 1030.64,1968.49 v1(1030.64,1950.82) ; v1(1463.93,2495.43) 1488.83,2495.43 D1.2@1492.13,2492.13
  Signal Layer 2 w10: v1(1030.64,1950.82) 1032.56,1948.91 1039.63,1948.91 1039.72,1948.82 1442.32,1948.82 1463.93,1970.42 v1@1463.93,2500
SYS: C12.1 C13.1 C14.1 C15.1 C16.1 C17.1 C29.1 C30.1 C31.1 J1.1 R13.2 U1.25 U3.2 | length 1655.4
  Top Layer w10: J1.1@165.35,2058.66 199.72,2024.29 199.72,2016.81 318.9,1897.64 376.08,1897.64 376.44,1897.28 493.23,1897.28 507.4,1897.28 537.4,1897.28 v1@573.94,1897.28 ; 564.96,1366.14 C29.1@618.11,1366.14 ; v1@567.4,1897.28 v1@573.94,1897.28 ; U3.2@602.76,1091.26 602.76,1150.52 C31.1@618.28,1166.04 618.11,1166.21 C30.1@618.11,1267.72 ; C30.1@614.17,1271.65 C30.1@618.11,1267.72 ; C29.1@618.11,1391.73 C29.1@618.11,1366.14 ; U1.25@913.5,1968.4 912.6,1967.5 912.6,1944.96 888.82,1921.18 878.07,1910.43 827.24,1910.43 814.09,1897.28 733.39,1897.28 653.66,1897.28 v1@573.94,1897.28 ; C30.1@618.11,1267.72 C29.1@618.11,1366.14
  Bottom Layer w10: 508,1406 v1@508,1427.64 ; v1(513.78,1427.64) 539.37,1453.23 539.37,1756.08 ; R13.2@521.65,1211.61 522.64,1212.6 564.96,1212.6 v1(576.77,1200.79)
  other v1: 483.78,1367.64 513.78,1367.64 543.78,1367.64 483.78,1397.64 513.78,1397.64 543.78,1397.64 483.78,1427.64 543.78,1427.64 507.4,1871.57 537.4,1871.57 567.4,1871.57 842.52,1872.05 507.4,1901.57 537.4,1901.57 567.4,1901.57 610.24,1931.1 689.72,1931.19 507.4,1931.57 537.4,1931.57 567.4,1931.57 769.45,1932.47
TS: J4.1 JP4.1 R3.1 R5.2 U1.16 | length 1096.9
  Top Layer w10: v1(845.59,2149.61) 845.59,2146.9 857.4,2135.09 857.4,2106.12 865.09,2098.43 876.04,2098.43
  Bottom Layer w10: J4.1@704.72,2856.3 843.31,2856.3 JP4.1@870.08,2829.53 934.25,2829.53 962.6,2801.18 962.6,2706.69 813.11,2557.2 R5.2@813.11,2189.96 R3.1@813.11,2149.61 v1(845.59,2149.61)
VBUS: L3.2 U4.23 U4.24 U4.25 U4.32 U4.33 | length 575.9
  Top Layer w6: v1@1194.88,1460.63 1219.12,1460.63 1219.3,1460.81 ; v1(1257.87,1614.17) 1257.87,1592.95 1267.72,1583.11 U4.24@1267.47,1582.86
  Top Layer w10: 1019.68,1602.36 1216.54,1602.36 1237.08,1602.36 1256.58,1582.86 U4.24@1267.47,1582.86
  Top Layer w20: v1@1204.72,1458.09 1197.42,1458.09 v1@1190.92,1464.59 ; 1219.3,1460.81 1215.52,1464.59 v1@1190.92,1464.59 ; v1@1190.92,1464.59 1183.07,1472.44 v1(1177.17,1472.44) 1185.02,1464.59 v1@1190.92,1464.59
  Bottom Layer w10: v1@1194.88,1460.63 1194.88,1549.21 1257.87,1612.2 v1(1257.87,1614.17)
  other v1: 1159.45,1460.63 1195.85,1462.13 1232.28,1590.55 1216.54,1604.33 1236.22,1614.17 1279.53,1614.17
pads on no net: FID1.1 FID2.1 FID3.1 FID4.1 FID5.1 FID6.1 H1.1 H2.1 H3.1 H4.1 H5.0 H6.0 H7.0 H8.0 J3.1 J3.2 J3.3 J3.4 J3.7 J3.8 J5.4 J5.5 J5.6 J5.7 J5.8 J5.9 J6.A2 J6.A3 J6.A8 J6.A10 J6.A11 J6.ALIGN1 J6.ALIGN2 J6.B2 J6.B3 J6.B8 J6.B10 J6.B11 J7.1 SH-J1.0 SH-J2.0 U1.6 U1.7 U1.12 U1.21 U2.4 U3.9@577.76,987.91 U4. U4.5 U4.6 U4.7 U4.13 U4.19 U4.36 U4.37 U5.C U6.7@434.06,1610.24 U6.7@469.49,1610.24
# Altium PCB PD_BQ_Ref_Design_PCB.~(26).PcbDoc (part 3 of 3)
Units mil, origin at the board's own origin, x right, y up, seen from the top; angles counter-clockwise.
Board outline 2000 x 3000 mil, 4 copper layers (Top Layer, Signal Layer 1, Signal Layer 2, Bottom Layer), stack 61.2 mil thick; 124 components, 53 nets, 359 pads, 494 vias.
Unrouted connection lines stored in the file: 227.

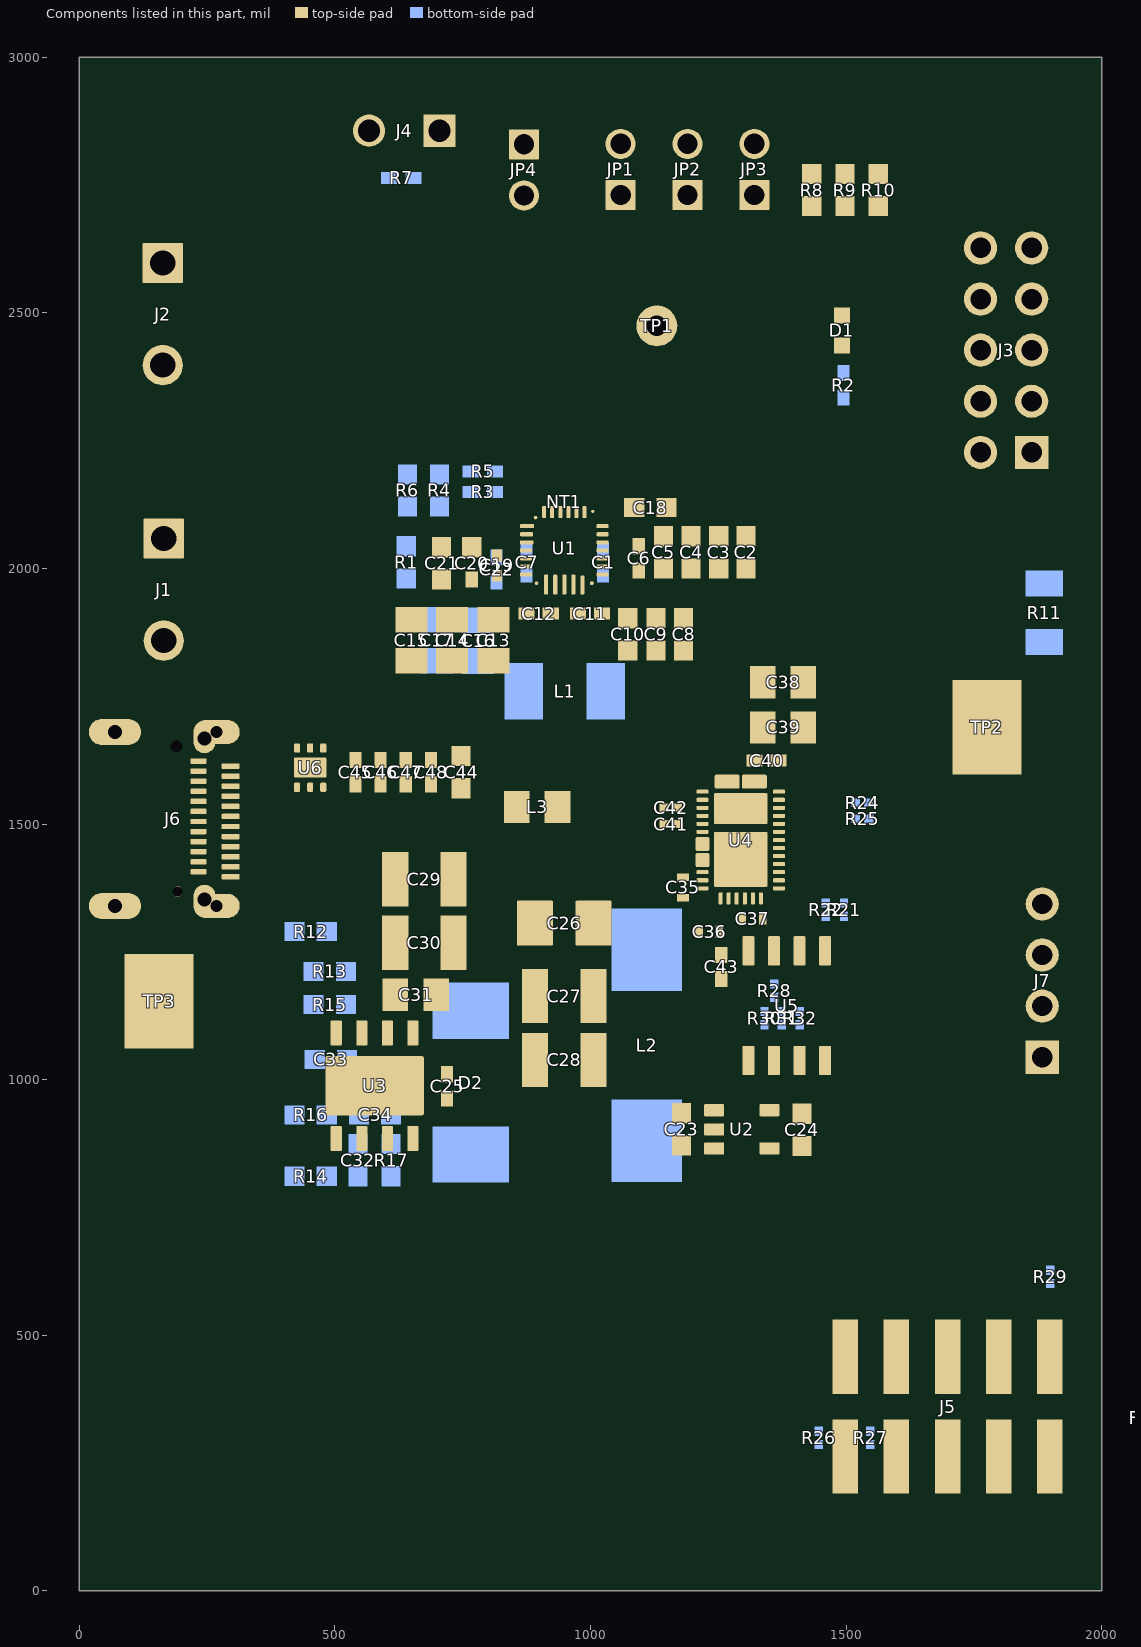
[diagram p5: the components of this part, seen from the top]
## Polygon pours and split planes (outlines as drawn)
NetC22_1 on Top Layer "TOP_LAYER_NETC22_1_P111" (solid, remove dead copper, pour order 111): 898.87,1975.98 848.82,1975.98 848.43,1976.38 848.43,1946.85 899.61,1946.85 898.87,1947.59
STAT on Top Layer "TOP_LAYER_STAT_P109" (solid, remove dead copper, pour order 109): 998.03,1975.98 998.03,1950.2 999.41,1948.82 1035.43,1948.82 1035.43,1975.92 1034.97,1976.38 1034.3,1975.7 998.73,1975.7
PPHV on Top Layer "TOP_LAYER_PPHV_P107" (solid, remove dead copper, pour order 107): 1000.69,2094.96 1000.27,2095.39 1000.27,2139.76 1039.37,2160.39 1040.32,2159.45 1049.21,2159.45 1049.21,2147.64 1033.46,2131.89 1033.46,2080.71 1035.23,2078.94 1013.78,2078.94 1013.78,2092.52 1011.33,2094.96
TS on Top Layer "TOP_LAYER_TS_P105" (solid, remove dead copper, pour order 105): 852.36,2131.89 885.71,2131.89 897.64,2119.97 897.64,2094.96 863.45,2094.96 863.18,2094.69 853.53,2104.33 852.36,2104.33
NetC1_2 on Top Layer "TOP_LAYER_NETC1_2_P103" (solid, remove dead copper, pour order 103): 960.63,2033.46 960.63,1992.13 1007.87,1992.13 1007.87,2033.46
NetC7_2 on Top Layer "TOP_LAYER_NETC7_2_P101" (solid, remove dead copper, pour order 101): 893.7,2033.46 893.7,1994.09 937.01,1994.09 937.01,2033.46
BAT on Top Layer "TOP_LAYER_BAT_P099" (solid, pour order 99): 769.68,2000 836.61,2000 836.61,1986.22 834.65,1984.25 769.68,1984.25 769.68,1999.76 769.45,2000
GND on Top Layer "tgaTOP_LAYER_GND_P081" (solid, pour order 97): 8.19,7.05 2008.19,7.05 2008.19,3007.05 8.19,3007.05
VBUS on Top Layer "Top Layer-VBUS" (solid, pour order 95): 1098.43,1598.43 1200.79,1598.43 1230.32,1568.9 1291.34,1568.9 1291.34,1663.38 1019.68,1663.39 950.79,1594.49 905.51,1594.49 905.51,1468.5 968.5,1468.5
NetC44_1 on Top Layer "Top Layer-NetC44_1" (solid, pour order 89): 427.17,1468.5 885.83,1468.5 885.83,1511.81 885.83,1594.49 787.4,1594.49 500,1594.49 488.19,1582.68 415.35,1582.68 391.73,1559.06 324.8,1559.05 324.8,1450.79 409.45,1450.79
SYS on Top Layer "Top Layer-SYS" (solid, pour order 40): 541.34,1196.85 590.55,1147.64 590.55,1102.36 614.17,1102.36 645.67,1133.86 649.61,1133.86 649.61,1448.82 458.66,1448.82 458.66,1338.58 541.34,1338.58
NetC25_2 on Top Layer "Top Layer-NetC25_2" (solid, pour order 85): 687.01,874.02 722.44,874.02 771.65,923.23 771.65,978.35 687.01,978.35
SYS on Top Layer "Top Layer-SYS 1" (solid, pour order 72): 255.91,1856.3 859.16,1856.3 900.5,1897.64 900.5,1944.88 551.18,1944.88 529.53,1966.54 297.24,1966.54 218.5,2045.28 218.5,2114.17 196.85,2114.17 112.2,2114.17 112.2,2000
LDO_1V5 on Top Layer "NONET_L-01_P-001" (solid, pour order 77): 1267.72,1342.52 1267.72,1366.14 1305.12,1366.14 1305.12,1303.15 1289.37,1303.15 1289.37,1320.87
AGND on Top Layer "NONET_L-01_P-001" (solid, pour order 76): 1401.57,2736.22 1598.43,2736.22 1598.43,2657.48 1401.57,2657.48
AGND on Top Layer "NONET_L-01_P-001" (solid, pour order 75): 946.85,2098.43 935.04,2098.43 935.04,2159.45 994.09,2159.45 994.09,2098.43 966.54,2098.43 966.54,2125.98 946.85,2125.98
BAT on Top Layer "Top Layer-BAT" (solid, pour order 66): 559.1,1956.65 649.61,1956.69 826.77,1956.69 854.33,1984.25 883.86,1984.25 883.86,2007.87 846.46,2007.87 826.77,1988.19 797.24,1988.19 785.43,2000 688.98,2000 521.65,2167.32 521.65,2250 305.65,2466 104.33,2466 104.33,2342.52 275.59,2342.52 413.39,2204.72 413.39,2102.36
PPHV on Top Layer "Top Layer-PPHV" (solid, pour order 51): 1269.68,1568.9 1346.46,1568.9 1346.46,1649.61 1377.95,1681.1 1377.95,1850.39 1377.95,2033.46 1043.31,2033.46 1043.31,1956.69 1232.28,1956.69 1269.68,1919.29
no net on Top Layer "NONET_L-01_P-001" (solid, pour order 49): 1377.95,1850.39
no net on Top Layer "NONET_L-01_P-001" (solid, pour order 48): 1377.95,1830.71
PPHV on Top Layer "NONET_L-01_P-001" (solid, pour order 14): 1090.98,2007.87 1116.42,2033.31 1324.71,2033.31 1324.88,1978.35 1012.91,1978.35 1012.91,2007.87
REGN on Top Layer "NONET_L-01_P-001" (solid, pour order 32): 1020.79,2031.5 1048.35,2031.5 1075.91,2059.06 1075.91,2070.87 1105.43,2100.39 1105.43,2137.8 1066.06,2137.8 1046.38,2118.11 1046.38,2049.21 1036.54,2039.37 1020.79,2039.37
PMID on Top Layer "NONET_L-01_P-001" (solid, pour order 42): 999.13,1944.88 1232.28,1944.88 1232.28,1870.08 1026.69,1870.08 999.13,1897.64
P3V3 on Top Layer "NONET_L-01_P-001" (solid, pour order 30): 1206.69,1377.95 1192.91,1364.17 1192.91,1348.43 1200.79,1348.43 1222.44,1370.08 1222.44,1377.95
VBUS on Top Layer "NONET_L-01_P-001" (solid, pour order 20): 1212.6,1446.85 1212.6,1474.41 1194.88,1474.41 1183.07,1486.22 1143.7,1486.22 1143.7,1446.85
LDO_1V5 on Top Layer "NONET_L-01_P-001" (solid, pour order 31): 1305.12,1293.31 1305.12,1358.27 1267.72,1358.27 1267.72,1342.52 1287.4,1342.52 1287.4,1293.31
LDO_3V3 on Top Layer "NONET_L-01_P-001" (solid, pour order 29): 1259.84,1350.39 1265.75,1344.49 1265.75,1291.34 1246.06,1291.34 1246.06,1318.9 1246.06,1350.39
PP5V on Top Layer "NONET_L-01_P-001" (solid, pour order 28): 1257.87,1354.33
PP5V on Top Layer "Top Layer-PP5V" (solid, pour order 17): 964.57,964.57 1104.33,964.57 1104.33,1379.92 1139.76,1415.35 1232.28,1415.35 1232.28,1442.91 1151.57,1442.91 1131.71,1462.78 1033.65,1462.78 1011.81,1440.94 964.57,1393.7
NetC1_2 on Bottom Layer "NONET_L-01_P-001" (solid, pour order 44): 994.09,1706.69 994.09,1811.02 1038.5,1811.02 1038.5,1706.69
NetC7_2 on Bottom Layer "NONET_L-01_P-001" (solid, pour order 43): 907.48,1706.69 907.48,1811.02 861.34,1811.02 861.34,1706.69
GND on Bottom Layer "BOTTOM_LAYER_GND_P090" (solid, remove dead copper, pour order 90): -15.68,11.67 1984.32,11.67 1984.32,3011.67 -15.68,3011.67
SYS on Bottom Layer "Top Layer-SYS 1" (solid, pour order 87): 494.09,1856.3 859.16,1856.3 900.5,1897.64 900.5,1944.88 551.18,1944.88 529.53,1966.54 494.09,1966.54
SYS on Bottom Layer "Bottom Layer-SYS" (solid, pour order 74): 604.33,1551.18 604.33,1702.76 604.33,1946.85 494.09,1946.85 494.09,1653.54 494.09,1590.55 458.66,1555.12 458.66,1338.58 568.9,1338.58 568.9,1515.75
NetC25_2 on Bottom Layer "Bottom Layer-NetC25_2" (solid, pour order 84): 687.01,795.28 954.72,795.28 1181.1,795.28 1181.1,911.42 771.65,911.42 771.65,978.35 687.01,978.35
NetU4_15 on Bottom Layer "NONET_L-01_P-001" (solid, pour order 78): 1241.94,1561.02 1241.94,1499.2 1346.14,1499.2 1346.47,1561.02
no net on Bottom Layer "NONET_L-01_P-001" (solid, pour order 37): 533.46,2041.34
PP5V on Bottom Layer "NONET_L-01_P-001" (solid, pour order 22): 964.57,1334.65 964.57,1116.14 1179.13,1116.14 1179.13,1334.65
VBUS on Bottom Layer "NONET_L-01_P-001" (solid, pour order 21): 1206.69,1446.85 1151.57,1446.85 1151.57,1561.02 1216.54,1625.98 1291.34,1625.98 1291.34,1568.9 1232.28,1568.9 1206.69,1543.31
AGND on Signal Layer 2 "SIGNAL_LAYER_2_AGND_P083" (solid, remove dead copper, pour order 83): 0,0 2000,0 2000,3000 0,3000
NetU4_15 on Signal Layer 2 "NONET_L-01_P-001" (solid, pour order 80): 1242.13,1559.66 1242.13,1500 1346.33,1500.18 1346.45,1559.66
NetC7_2 on Signal Layer 2 "NONET_L-01_P-001" (solid, pour order 45): 894.8,1887.8 867.24,1887.8 867.24,1919.29 894.8,1946.85 894.8,2023.62 936.14,2023.62 936.14,1931.1
NetC1_2 on Signal Layer 2 "NONET_L-01_P-001" (solid, pour order 46): 1005.04,1887.8 1032.6,1887.8 1032.6,1919.29 1005.04,1946.85 1005.04,2023.62 963.7,2023.62 963.7,1931.1
GND on Signal Layer 1 "SIGNAL_LAYER_1_GND_P082" (solid, pour order 82): 0,0 2000,0 2000,3000 0,3000
NetU4_15 on Signal Layer 1 "NONET_L-01_P-001" (solid, pour order 79): 1242.13,1561.02 1346.46,1561.02 1346.07,1560.64 1346.07,1500.18 1242.13,1500.18

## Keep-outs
Keep-Out Layer:
  text ".Layer_Name" at 577,-858.49 h60

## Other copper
Top Layer:
  pour cut-out: 1000,1698.82 1000,1818.9 899.61,1818.9 899.61,1698.82
  text ".Layer_Name" at 577,-858.49 h60
Signal Layer 1:
  pour cut-out: 854.33,1820.87 1045.28,1820.87 1045.28,1698.82 856.3,1698.82
Signal Layer 2:
  pour cut-out: 854.33,1858.27 1045.28,1858.27 1045.28,1696.85 856.3,1696.85
Bottom Layer:
  pour cut-out: 854.33,1822.83 854.33,1696.85 1045.28,1696.85 1045.28,1822.83
  text ".Layer_Name" at 577,-858.49 h60

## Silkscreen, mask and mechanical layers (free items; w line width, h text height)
Top Overlay:
  lines w5: 386.81,1665.35 386.81,1773.62 386.81,2218.5 1237.2,2218.5 1492.13,2218.5 1492.13,765.75 386.81,765.75 386.81,944.88 386.81,1668.31 ; 830.71,1694.88 846.46,1710.63 860.24,1724.41 860.24,1866.14 874.02,1879.92 ; 1027.56,1879.92 1037.4,1870.08 1037.4,1724.41 1062.99,1698.82 1069.88,1691.93 ; 1114.17,1964.57 1127.95,1950.79 1242.13,1950.79 ; 1183.07,2098.43 1204.72,2120.08 ; 1214.57,2098.43 1238.19,2122.05 ; 1261.81,2098.43 1287.4,2124.02 ; 1314.96,2100.39 1340.55,2125.98 ; 1204.72,2120.08 1204.72,2120.08
  text "'.PRJ_Number'.PCB_Rev" at 1421.26,2881.89 h108.27
  text "up to 5A" at 45.28,2720.47 h60
  text "EXT_TS" at 542.43,2647.52 h60
  text "2S" at 1041.71,2630.06 h60
  text "4S" at 1306.21,2629.05 h60
  text "3S" at 1173.61,2628.46 h60
  text "TS" at 849.52,2623.14 h60
  text "GND" at 426.07,2528.65 h60 r90
  text "STAT" at 1296.37,2487.32 h60
  text "PPHV" at 1058.18,2314.09 h60
  text "BATT" at 437.88,2296.37 h60 r90
  text "up to 10A" at 53.15,2185.22 h60
  text "SYS" at 441.82,2010.94 h60 r90
  text "USB2ANY" at 1689.09,1908.57 h60
  text "Connector" at 1622.16,1854.44 h60
  text "GND" at 439.85,1804.24 h60 r90
  text "GND" at 1745.19,1463.69 h60
  text "GND" at 79.83,927.28 h60
  text "Aardvark" at 1655.62,626.09 h60
  text "Connector" at 1622.16,566.06 h60
  text "Total Solution Size" at 391.84,548.34 h60
  text "USB-PD-CHG-EVM-01" at 358,328.74 h108
  text ".Layer_Name" at 577,-858.49 h60
Bottom Overlay:
  text ".Layer_Name" at 577,-858.49 h60
Top Paste:
  text ".Layer_Name" at 577,-858.49 h60
Bottom Paste:
  text ".Layer_Name" at 577,-858.49 h60
Top Solder:
  text ".Layer_Name" at 577,-858.49 h60
  text ".Layer_Name" at 577,-858.49 h60
Bottom Solder:
  text ".Layer_Name" at 577,-858.49 h60
Drill Guide:
  text ".Layer_Name" at 577,-858.49 h60
M1 Board Outline:
  the board outline again, w10
  text ".Layer_Name" at 577,-858.49 h60
M2 Board Dimensions:
  rectangle: 0,-275 125,-150
  rectangle: 125,-400 500,-275
  lines w7: 0,-275 1000,-275 ; 125,-400 125,-150 ; 250,-400 250,-150 ; 500,-400 500,-150 ; 750,-400 750,-150 ; 0,-400 1000,-400 1000,-150 0,-150 0,-400
  text ".Layer_Name" at 577,-858.49 h60
M3 3D STEP Top:
  text ".Layer_Name" at 577,-858.49 h60
M4 3D STEP Bottom:
  text ".Layer_Name" at 577,-858.49 h60
M5 Assembly Top:
  lines w10: -292,-930.17 6308,-930.17 ; -292,-726.83 6310,-726.83 ; -292,-523.5 -292,-1133.5 3713,-1133.5 6310,-1133.5 6310,-523.5 -291.5,-523.5 -291.5,-1133.5 1284,-1133.5 ; 2173,-1133.5 2173,-523.5 ; 3440,-726.83 3440,-523.5 ; 4280,-726.83 4280,-523.5 ; 4902,-1140 4902,-937.17
  text "COMPONENTS MARKED 'DNP' SHOULD NOT BE POPULATED." at 1153.5,-318.5 h60
  text "ASSEMBLY VARIANT:" at 1153,-434 h60
  text ".VariantName" at 2189,-434 h60
  text "PCB VIEWED FROM TOP SIDE" at -228.5,-655.67 h60
  text "BOARD #:" at 2248,-655.67 h60
  text ".PRJ_Number" at 2793.5,-655.67 h60
  text "REV:" at 3638,-655.67 h60
  text ".PCB_Rev" at 3929.5,-655.67 h60
  text "SVN REV:" at 4476,-655.67 h60
  text ".VersionControl_RevNumber" at 4982,-655.67 h60
  text "TID #:" at 2248,-859 h60
  text ".TID" at 2793.5,-859 h60
  text "PLOT NAME =" at -228.5,-1064.34 h60
  text ".plot_File_Name" at 577,-1064.34 h60
  text "GENERATED    :" at 2250,-1064.34 h60
  text ".Print_Date" at 3119.5,-1064.34 h60
  text ".Print_Time" at 3848.5,-1064.34 h60
  text "TEXAS INSTRUMENTS" at 5113,-1064.34 h60
M6 Assembly Bottom:
  lines w10: -292.5,-727.33 6309.5,-727.33 ; -290.5,-930.67 6309.5,-930.67 ; 1115.5,-1140.5 1115.5,-937.67 ; 1737.5,-727.33 1737.5,-524 ; 2577.5,-727.33 2577.5,-524 ; 3844.5,-1134 3844.5,-524 ; 4733.5,-1134 6309,-1134 6309,-524 -292.5,-524 -292.5,-1134 2304.5,-1134 6309.5,-1134 6309.5,-524
  text "COMPONENTS MARKED 'DNP' SHOULD NOT BE POPULATED." at 6102,-318 h60
  text ".VariantName" at 5058,-434 h60
  text "ASSEMBLY VARIANT:" at 6097,-434 h60
  text ".VersionControl_RevNumber" at 1035.5,-656.17 h60
  text "SVN REV:" at 1541.5,-656.17 h60
  text ".PCB_Rev" at 2088,-656.17 h60
  text "REV:" at 2379.5,-656.17 h60
  text ".PRJ_Number" at 3224,-656.17 h60
  text "BOARD #:" at 3769.5,-656.17 h60
  text "PCB VIEWED FROM BOTTOM SIDE" at 6246,-656.17 h60
  text ".TID" at 3224,-859.5 h60
  text "TID #:" at 3769.5,-859.5 h60
  text "TEXAS INSTRUMENTS" at 904.5,-1064.84 h60
  text ".Print_Time" at 2169,-1064.84 h60
  text ".Print_Date" at 2898,-1064.84 h60
  text "GENERATED    :" at 3767.5,-1064.84 h60
  text ".plot_File_Name" at 5440.5,-1064.84 h60
  text "PLOT NAME =" at 6246,-1064.84 h60
M9 Title Sheet:
  drawing of 57 lines, arcs and shapes, not listed
  text "1" at 739.84,8036.5 h70
  text "2" at 3235.5,8036.5 h70
  text "3" at 5724.84,8036.5 h70
  text "4" at 8231.51,8036.5 h70
  text "5" at 10730.5,8036.5 h70
  text "6" at 13235.5,8036.5 h70
  text "A" at -416.5,6893.5 h70
  text "A" at 14383.5,6893.5 h70
  text "B" at -416.5,4513.5 h70
  text "B" at 14383.5,4513.5 h70
  text "C" at -416.5,2138.5 h70
  text "C" at 14383.5,2138.5 h70
  text "PROJECT TITLE:" at 11343.5,277.5 h45
  text ".PRJ_Title" at 11393.5,144.17 h70
  text "DESIGNED FOR:" at 11343.5,-23.5 h45
  text ".PRJ_Customer" at 11393.5,-163.5 h70
  text "D" at -416.5,-231.5 h70
  text "D" at 14383.5,-231.5 h70
  text "FILE NAME:" at 11343.5,-323.5 h45
  text ".PCB_File_Name_No_Path" at 11393.5,-443.5 h70
  text "Texas Instruments (TI) and/or its licensors do not warrant the accuracy or completeness of this specification" at 6374,-605.34 h45
  text "ENGINEER:" at 11343.5,-613.5 h45
  text "LAYOUT BY:" at 12848.5,-613.5 h45
  text "or any information contained therein. TI and/or its licensors do not warrant that this design will meet" at 6329.01,-718 h45
  text ".PRJ_Engineer" at 11393.5,-768.49 h70
  text ".PCB_Layout" at 12899,-768.49 h70
  text "the specifications, will be suitable for your application or fit for any particular purpose, or will operate in" at 6329.01,-830.67 h45
  text ".Layer_Name" at 577,-858.49 h60
  text "ALTIUM DESIGNER VERSION:" at 12848.5,-923.5 h45
  text "an implementation. TI and/or its licensors do not warrant that the design is production worthy. You should" at 6329.01,-943.33 h45
  text "completely validate and test your design implementation to confirm the system functionality for your application." at 6374,-1056 h45
  text ".print_Scale" at 11393.5,-1056.83 h70
  text ".Application_BuildNumber" at 12899,-1056.83 h70
  text "1" at 739.84,-1263.5 h70
  text "2" at 3235.5,-1263.5 h70
  text "3" at 5724.84,-1263.5 h70
  text "4" at 8231.51,-1263.5 h70
  text "5" at 10730.5,-1263.5 h70
  text "6" at 13235.5,-1263.5 h70
M10 Fab Notes:
  drawing of 189 lines, arcs and shapes, not listed
  text "DESIGN INFORMATION" at 12382.02,6356.17 h60
  text "MIN. TRACK WIDTH:" at 11737.46,6224.05 h60
  text "8" at 12833.7,6224.05 h60
  text "MIL" at 12988.46,6224.05 h60
  text "MIN. CLEARANCE:" at 11737.46,6099.92 h60
  text "0.2" at 12773.7,6099.93 h60
  text "mm" at 12988.46,6099.92 h60
  text "MIN. VIA PAD SIZE:" at 11737.46,5975.8 h60
  text "24" at 12803.71,5975.8 h60
  text "MIL" at 12988.46,5975.8 h60
  text "0.05mm (2MIL)" at 12432.46,5845.9 h60
  text "MINIMUM ANNULAR RING" at 11408.23,5837.67 h60
  text "EXTERNAL" at 13140.46,5837.67 h60
  text "PER" at 11608.23,5727.55 h60
  text "IPC-D-275 CLASS 2 LEVEL C" at 11828.23,5727.54 h60
  text "MIL, HOLES" at 13316.46,5627.07 h60
  text "+/-" at 12924,5618.48 h60
  text "+/-" at 13778,5618.48 h60
  text "REGISTRATION TOLERANCES:" at 11408.23,5617.42 h60
  text "METAL" at 12608,5617.42 h60
  text "5" at 13184.2,5617.42 h60
  text "3" at 14017.2,5617.42 h60
  text "MIL" at 14133.46,5617.42 h60
  text "HOLE SIZE TOLERANCE (UNLESS OTHERWISE SPECIFIED):" at 11408.23,5519.1 h60
  text "+/-" at 13778,5516.23 h60
  text "3" at 14017.2,5515.17 h60
  text "MIL" at 14133.46,5515.17 h60
  text "MATERIAL:" at 11333.46,5377.52 h60
  text "FR-4 High Tg" at 12319.9,5249 h60
  text "X" at 12175.46,5241.01 h60
  text "FR-408" at 11754.46,5236.49 h60
  text "OTHER" at 13242.46,5236.49 h60
  text "62 MIL (1.6mm) +/-10%" at 12074.56,5093.46 h60
  text "X" at 11954.46,5091.01 h60
  text "THICKNESS:" at 11408.23,5085.24 h60
  text "OTHER" at 13359.46,5085.24 h60
  text "TOLERANCE:" at 11408.23,4946.92 h60
  text "X" at 12256.46,4946.92 h60
  text "ANSI IPC-6012 TYPE 3 CLASS 2" at 12434.48,4946.92 h60
  text "OTHER +/-" at 12434.46,4802.73 h60
  text "BOW & TWIST:" at 11408.23,4657.54 h60
  text "X" at 12256.46,4657.54 h60
  text "ANSI IPC-6012 TYPE 3 CLASS 2" at 12434.48,4657.54 h60
  text "OTHER +/-" at 12434.46,4510.85 h60
  text "DRILLING:" at 11333.46,4380.23 h60
  text "NC_DRILL FILES" at 13094.46,4275.04 h60
  text "REFERENCE:" at 11408.23,4271.1 h60
  text "X" at 12065.46,4271.01 h60
  text "AS SHOWN" at 12243.46,4271.1 h60
  text "X" at 12966.46,4271.1 h60
  text "OTHER" at 13392.46,4128.85 h60
  text "PTH COPPER THICKNESS:" at 11407.91,4125.32 h60
  text "X" at 12547.14,4125.32 h60
  text "20-30 um" at 12675.14,4125.32 h60
  text "BOARD FINISH:" at 11333.46,3977.73 h60
  text "SILKSCREEN:" at 11488.68,3867.6 h60
  text "X" at 12446.46,3867.6 h60
  text "TOP" at 12563.46,3867.6 h60
  text "X" at 12956.46,3867.6 h60
  text "BOTTOM" at 13074.46,3867.6 h60
  text "SILKSCREEN COLOR:" at 11488.68,3712.41 h60
  text "X" at 12445.46,3712.41 h60
  text "WHITE" at 12563.46,3712.41 h60
  text "OTHER" at 13074.46,3712.41 h60
  text "X" at 12576.46,3568.96 h60
  text "GREEN" at 12694.46,3568.96 h60
  text "OTHER" at 13312.46,3568.96 h60
  text "SOLDER RESIST COLOR:" at 11488.68,3562.1 h60
  text "X" at 12576.46,3414.71 h60
  text "MATTE" at 12694.46,3414.71 h60
  text "SEMI-GLOSS" at 13312,3414.07 h60
  text "IMMERSION GOLD (ENIG)" at 12394.46,3241.94 h60
  text "ENEPIG" at 13732,3234.72 h60
  text "SURFACE FINISH:" at 11333.46,3233.72 h60
  text "X" at 12216.46,3233.72 h60
  text "IMM. TIN/SILVER OR EQUIV" at 11663,3096.4 h60
  text "OTHER" at 13094.46,3092.47 h60
  text "ARRAY/PANEL:" at 11333.46,2937.09 h60
  text "CUT AND TRIM PER M1 BOARD OUTLINE" at 12394.46,2928.87 h60
  text "N.C. ROUTE" at 12394.46,2792.9 h60
  text "X" at 13082.46,2792.9 h60
  text "V. SCORE" at 13260.46,2792.9 h60
  text "CERTIFICATION:" at 11333.46,2663.77 h60
  text "MATERIALS AND WORKMANSHIP FOR ALL PCBS" at 12058.46,2663.77 h60
  text "TO MEET OR EXCEED THE REQUIREMENTS OF:" at 12058.46,2569.71 h60
  text "X" at 11695.97,2441.08 h60
  text "ANSI IPC-A-600F CLASS ->" at 11823.96,2441.08 h60
  text "X" at 13471.97,2441.08 h60
  text "2" at 13581.96,2441.08 h60
  text "1" at 13266.96,2439.58 h60
  text "3" at 13935.96,2439.58 h60
  text "X" at 12507.97,2293.39 h60
  text "RoHS" at 12635.96,2293.39 h60
  text "OTHER" at 13280.36,2293.39 h60
  text "PER ORDER" at 13677.42,2293.39 h60
  text "ALL BOARDS MUST MEET OR EXCEED UL94-V0 REQUIREMENTS." at 11361,2139.57 h60
  text "PCB MUST BEAR THE UL94V-0 UL REGISTERED MATERIAL ID NUMBER" at 11361,2023.5 h60
  text "ADDITIONAL REQUIREMENTS:" at 11333.46,1854.08 h60
  text "MICROSECTION:" at 11408.23,1746.95 h60
  text "YES" at 12313.96,1746.95 h60
  text "REQUIRED" at 13175.46,1602.62 h60
  text "BARE BOARD ELEC. TEST:" at 11408.23,1599.76 h60
  text "NONE" at 12713.96,1599.76 h60
  text "X" at 13057.46,1599.76 h60
  text "PER ORDER" at 13767.46,1599.76 h60
  text "XX MIL VIAS REQUIRE NON-CONDUCTIVE FILL AND PLANARIZE" at 11576.38,1394.82 h59
  text "XX MIL VIAS REQUIRE CONDUCTIVE FILL AND PLANARIZE" at 11584.38,1290.84 h60
  text "OUTER XX MIL TRACES REQUIRE 50 OHM SINGLE-ENDED IMPEDANCE" at 11583.39,1127.46 h58
  text "LAYER 2 & 3 (INNER LAYERS) XX MIL WIDE, XX MIL SPACE / TRACES REQUIRE 100 OHM DIFFERENTIAL IMPEDANCE" at 11575.39,891.74 h60
  text ".Layer_Name" at 577,-858.49 h60
M11 Gerber Information:
  lines w10: -292,-930.17 6308,-930.17 ; -292,-726.83 6310,-726.83 ; -292,-523.5 -292,-1133.5 3713,-1133.5 6310,-1133.5 6310,-523.5 -291.5,-523.5 -291.5,-1133.5 1284,-1133.5 ; 2173,-1133.5 2173,-523.5 ; 3440,-726.83 3440,-523.5 ; 4280,-726.83 4280,-523.5 ; 4902,-1140 4902,-937.17
  text "ALL ARTWORK VIEWED FROM TOP SIDE" at -228.5,-655.67 h60
  text "BOARD #:" at 2248,-655.67 h60
  text ".PRJ_Number" at 2793.5,-655.67 h60
  text "REV:" at 3638,-655.67 h60
  text ".PCB_Rev" at 3929.5,-655.67 h60
  text "SVN REV:" at 4476,-655.67 h60
  text ".VersionControl_RevNumber" at 4982,-655.67 h60
  text "LAYER NAME =" at -228.5,-858.49 h60
  text "TID #:" at 2248,-859 h60
  text ".TID" at 2793.5,-859 h60
  text "PLOT NAME =" at -228.5,-1064.34 h60
  text ".plot_File_Name" at 577,-1064.34 h60
  text "GENERATED    :" at 2250,-1064.34 h60
  text ".Print_Date" at 3119.5,-1064.34 h60
  text ".Print_Time" at 3848.5,-1064.34 h60
  text "TEXAS INSTRUMENTS" at 5113,-1064.34 h60
M12 Stackup:
  drawing of 295 lines, arcs and shapes, not listed
  text "Layer" at 9811.59,7649.94 h60
  text "Name" at 10221.51,7649.94 h60
  text "Material" at 11161.25,7649.94 h60
  text "Thickness" at 12021.02,7649.94 h60
  text "Constant" at 12670.85,7649.94 h60
  text "Board Layer Stack" at 13240.71,7649.94 h60
  text "1" at 9811.59,7529.94 h60
  text "Top Overlay" at 10221.51,7529.94 h60
  text "2" at 9811.59,7409.94 h60
  text "Top Solder" at 10221.51,7409.94 h60
  text "Solder Resist" at 11161.25,7409.94 h60
  text "0.40mil" at 12021.02,7409.94 h60
  text "3.5" at 12670.85,7409.94 h60
  text "3" at 9811.59,7289.94 h60
  text "Top Layer" at 10221.51,7289.94 h60
  text "Copper" at 11161.25,7289.94 h60
  text "2.80mil" at 12021.02,7289.94 h60
  text "4" at 9811.59,7169.94 h60
  text "Dielectric 1" at 10221.51,7169.94 h60
  text "FR-4 High TG" at 11161.25,7169.94 h60
  text "12.00mil" at 12021.02,7169.94 h60
  text "4.2" at 12670.85,7169.94 h60
  text "5" at 9811.59,7049.94 h60
  text "Signal Layer 1" at 10221.51,7049.94 h60
  text "Copper" at 11161.25,7049.94 h60
  text "2.80mil" at 12021.02,7049.94 h60
  text "6" at 9811.59,6929.94 h60
  text "Dielectric2" at 10221.51,6929.94 h60
  text "FR-4 High TG" at 11161.25,6929.94 h60
  text "26.00mil" at 12021.02,6929.94 h60
  text "4.2" at 12670.85,6929.94 h60
  text "7" at 9811.59,6809.94 h60
  text "Signal Layer 2" at 10221.51,6809.94 h60
  text "Copper" at 11161.25,6809.94 h60
  text "2.80mil" at 12021.02,6809.94 h60
  text "8" at 9811.59,6689.94 h60
  text "Dielectric3" at 10221.51,6689.94 h60
  text "FR-4 High TG" at 11161.25,6689.94 h60
  text "12.00mil" at 12021.02,6689.94 h60
  text "4.2" at 12670.85,6689.94 h60
  text "9" at 9811.59,6569.94 h60
  text "Bottom Layer" at 10221.51,6569.94 h60
  text "Copper" at 11161.25,6569.94 h60
  text "2.80mil" at 12021.02,6569.94 h60
  text "10" at 9811.59,6449.94 h60
  text "Bottom Solder" at 10221.51,6449.94 h60
  text "Solder Resist" at 11161.25,6449.94 h60
  text "0.40mil" at 12021.02,6449.94 h60
  text "3.5" at 12670.85,6449.94 h60
  text "11" at 9811.59,6329.94 h60
  text "Bottom Overlay" at 10221.51,6329.94 h60
  text ".Layer_Name" at 577,-858.49 h60
M13 Component Bodies Top:
  text ".Layer_Name" at 577,-858.49 h60
M14 Component Bodies Bottom:
  text ".Layer_Name" at 577,-858.49 h60
M15 Courtyards Top:
  text ".Layer_Name" at 577,-858.49 h60
M16 Courtyards Bottom:
  text ".Layer_Name" at 577,-858.49 h60
Drill Drawing:
  circle w10: c5363.72,3273.62 r16.58
  circle w10: c5363.72,3273.62 r27.63
  circle w10: c5363.72,3149.3 r27.63
  lines w10: 5336.09,1878.47 5391.34,1878.47 5391.34,1933.73 5336.09,1933.73 5336.09,1878.47 ; 5336.09,2016.61 5349.9,2016.61 5349.9,2002.79 5377.53,2002.79 5377.53,2016.61 5391.34,2016.61 5391.34,2044.23 5377.53,2044.23 5377.53,2058.05 5349.9,2058.05 5349.9,2044.23 5336.09,2044.23 5336.09,2016.61 ; 5336.09,2127.11 5363.72,2140.93 5391.34,2127.11 5377.53,2154.74 5391.34,2182.37 5363.72,2168.55 5336.09,2182.37 5349.9,2154.74 5336.09,2127.11 ; 5336.09,2306.69 5391.34,2306.69 5363.72,2251.43 5336.09,2306.69 ; 5336.09,2403.38 5363.72,2375.75 5391.34,2403.38 5363.72,2431.01 5336.09,2403.38 ; 5336.09,2500.07 5391.34,2500.07 5391.34,2555.33 5336.09,2555.33 5336.09,2500.07 ; 5336.09,2624.39 5336.09,2638.21 5349.9,2652.02 5336.09,2665.83 5336.09,2679.65 5349.9,2679.65 5363.72,2665.83 5377.53,2679.65 5391.34,2679.65 5391.34,2665.83 5377.53,2652.02 5391.34,2638.21 5391.34,2624.39 5377.53,2624.39 5363.72,2638.21 5349.9,2624.39 5336.09,2624.39 ; 5336.09,2748.71 5363.72,2762.53 5391.34,2748.71 5377.53,2776.34 5391.34,2803.97 5363.72,2790.15 5336.09,2803.97 5349.9,2776.34 5336.09,2748.71 ; 5336.09,2886.85 5349.9,2886.85 5363.72,2873.03 5377.53,2886.85 5391.34,2886.85 5377.53,2900.66 5391.34,2914.47 5377.53,2914.47 5363.72,2928.29 5349.9,2914.47 5336.09,2914.47 5349.9,2900.66 5336.09,2886.85 ; 5336.09,3052.61 5391.34,3052.61 5363.72,2997.35 5336.09,3052.61 ; 5336.09,3384.13 5349.9,3384.13 5363.72,3370.31 5377.53,3384.13 5391.34,3384.13 5377.53,3397.94 5391.34,3411.75 5377.53,3411.75 5363.72,3425.57 5349.9,3411.75 5336.09,3411.75 5349.9,3397.94 5336.09,3384.13 ; 5347.14,2511.12 5380.29,2511.12 5380.29,2544.28 5347.14,2544.28 5347.14,2511.12 ; 5347.14,2759.76 5363.72,2768.05 5380.29,2759.76 5372.01,2776.34 5380.29,2792.92 5363.72,2784.63 5347.14,2792.92 5355.43,2776.34 5347.14,2759.76 ; 5347.14,2892.37 5355.43,2892.37 5363.72,2884.08 5372.01,2892.37 5380.29,2892.37 5372.01,2900.66 5380.29,2908.95 5372.01,2908.95 5363.72,2917.24 5355.43,2908.95 5347.14,2908.95 5355.43,2900.66 5347.14,2892.37 ; 5347.14,3041.56 5380.29,3041.56 5363.72,3008.4 5347.14,3041.56
  lines w12: 5286,1841.18 8517.49,1841.18 ; 5286,3457.34 8517.49,3457.34 ; 5623.86,1716.86 5623.86,3581.66 ; 5955.86,1716.86 5955.86,3581.66 ; 6592.43,1716.86 6592.43,3581.66 ; 6851.57,1716.86 6851.57,3581.66 ; 7226.72,1716.86 7226.72,3581.66 ; 7951.05,1716.86 7951.05,3581.66 ; 5286,1716.86 8517.49,1716.86 8517.49,3581.66 5286,3581.66 5286,1716.86
  text "Symbol" at 5360.59,3494.63 h72
  text "Quantity" at 5661.16,3494.63 h72
  text "Finished Hole Size" at 5993.16,3494.63 h72
  text "Plated" at 6629.72,3494.63 h72
  text "Hole Type" at 6888.86,3494.63 h72
  text "Drill Layer Pair" at 7264.02,3494.63 h72
  text "Hole Tolerance" at 7988.35,3494.63 h72
  text "1" at 5661.16,3370.31 h60
  text "23.62mil (0.600mm)" at 5993.16,3370.31 h60
  text "NPTH" at 6629.72,3370.31 h60
  text "Round" at 6888.86,3370.31 h60
  text "Top Layer - Bottom Layer" at 7264.02,3370.31 h60
  text "+/-1.18mil" at 7988.35,3370.31 h60
  text "10" at 5661.16,3245.99 h60
  text "7.87mil (0.200mm)" at 5993.16,3245.99 h60
  text "PTH" at 6629.72,3245.99 h60
  text "Round" at 6888.86,3245.99 h60
  text "Top Layer - Bottom Layer" at 7264.02,3245.99 h60
  text "448" at 5661.16,3121.67 h60
  text "10.00mil (0.254mm)" at 5993.16,3121.67 h60
  text "PTH" at 6629.72,3121.67 h60
  text "Round" at 6888.86,3121.67 h60
  text "Top Layer - Bottom Layer" at 7264.02,3121.67 h60
  text "24" at 5661.16,2997.35 h60
  text "11.81mil (0.300mm)" at 5993.16,2997.35 h60
  text "PTH" at 6629.72,2997.35 h60
  text "Round" at 6888.86,2997.35 h60
  text "Top Layer - Bottom Layer" at 7264.02,2997.35 h60
  text "12" at 5661.16,2873.03 h60
  text "15.00mil (0.381mm)" at 5993.16,2873.03 h60
  text "PTH" at 6629.72,2873.03 h60
  text "Round" at 6888.86,2873.03 h60
  text "Top Layer - Bottom Layer" at 7264.02,2873.03 h60
  text "4" at 5661.16,2748.71 h60
  text "39.37mil (1.000mm)" at 5993.16,2748.71 h60
  text "PTH" at 6629.72,2748.71 h60
  text "Round" at 6888.86,2748.71 h60
  text "Top Layer - Bottom Layer" at 7264.02,2748.71 h60
  text "19" at 5661.16,2624.39 h60
  text "40.00mil (1.016mm)" at 5993.16,2624.39 h60
  text "PTH" at 6629.72,2624.39 h60
  text "Round" at 6888.86,2624.39 h60
  text "Top Layer - Bottom Layer" at 7264.02,2624.39 h60
  text "2" at 5661.16,2500.07 h60
  text "43.31mil (1.100mm)" at 5993.16,2500.07 h60
  text "PTH" at 6629.72,2500.07 h60
  text "Round" at 6888.86,2500.07 h60
  text "Top Layer - Bottom Layer" at 7264.02,2500.07 h60
  text "4" at 5661.16,2375.75 h60
  text "49.21mil (1.250mm)" at 5993.16,2375.75 h60
  text "PTH" at 6629.72,2375.75 h60
  text "Round" at 6888.86,2375.75 h60
  text "Top Layer - Bottom Layer" at 7264.02,2375.75 h60
  text "1" at 5661.16,2251.43 h60
  text "19.69mil (0.500mm)" at 5993.16,2251.43 h60
  text "NPTH" at 6629.72,2251.43 h60
  text "Slot" at 6888.86,2251.43 h60
  text "Top Layer - Bottom Layer" at 7264.02,2251.43 h60
  text "+/-1.18mil" at 7988.35,2251.43 h60
  text "2" at 5661.16,2127.11 h60
  text "23.62mil (0.600mm)" at 5993.16,2127.11 h60
  text "PTH" at 6629.72,2127.11 h60
  text "Slot" at 6888.86,2127.11 h60
  text "Top Layer - Bottom Layer" at 7264.02,2127.11 h60
  text "+/-1.97mil" at 7988.35,2127.11 h60
  text "2" at 5661.16,2002.79 h60
  text "27.56mil (0.700mm)" at 5993.16,2002.79 h60
  text "PTH" at 6629.72,2002.79 h60
  text "Slot" at 6888.86,2002.79 h60
  text "Top Layer - Bottom Layer" at 7264.02,2002.79 h60
  text "+/-1.97mil" at 7988.35,2002.79 h60
  text "2" at 5661.16,1878.47 h60
  text "27.56mil (0.700mm)" at 5993.16,1878.47 h60
  text "PTH" at 6629.72,1878.47 h60
  text "Slot" at 6888.86,1878.47 h60
  text "Top Layer - Bottom Layer" at 7264.02,1878.47 h60
  text "+/-1.97mil" at 7988.35,1878.47 h60
  text "531 Total" at 5661.16,1754.15 h60
  text "Slot definitions :" at 5360.59,1667.13 h60
  text "Routed Path Length" at 5811.31,1667.13 h60
  text "= Calculated from tool start centre position to tool end centre position." at 6351.05,1667.13 h60
  text "Hole Length" at 5811.31,1617.4 h60
  text "= Routed Path Length + Tool Size = Slot length as defined in the PCB layout" at 6151.24,1617.4 h60
  text ".Layer_Name" at 577,-858.49 h60
M17 Embedded Cavity:
  text ".Layer_Name" at 577,-858.49 h60
M18 Embedded Assembly:
  text ".Layer_Name" at 577,-858.49 h60
M19 Embedded Keepout:
  text ".Layer_Name" at 577,-858.49 h60

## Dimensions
1492.13,2218.5 to 1492.13,765.75 on Top Overlay
386.81,765.75 to 1492.13,765.75 on Top Overlay
0,-400 to 1000,-400 on M2 Board Dimensions
0,0 to 0,3000 on M2 Board Dimensions
0,0 to 2000,0 on M2 Board Dimensions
